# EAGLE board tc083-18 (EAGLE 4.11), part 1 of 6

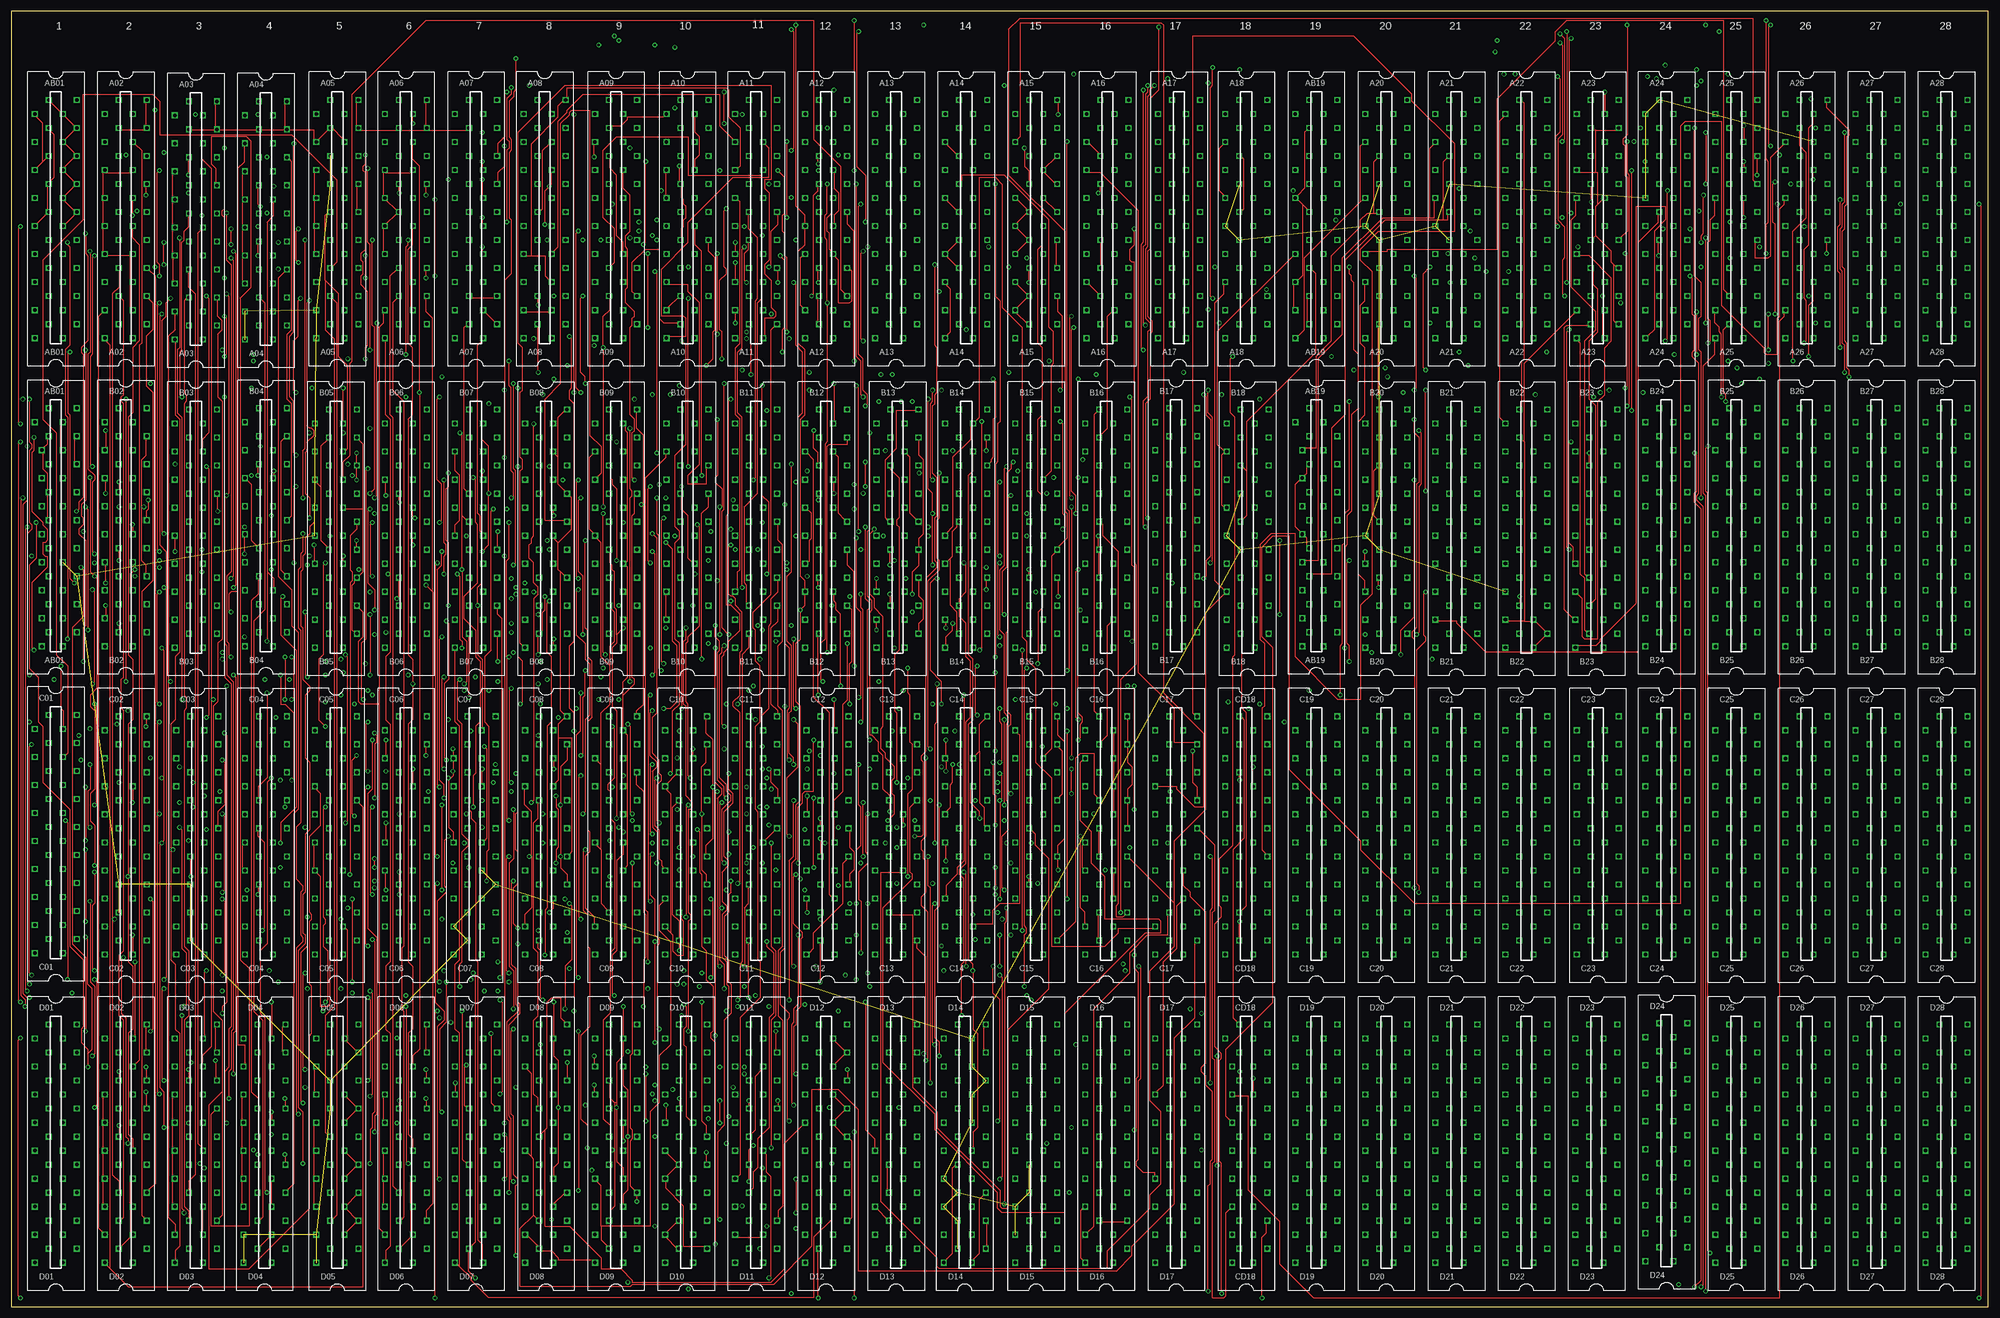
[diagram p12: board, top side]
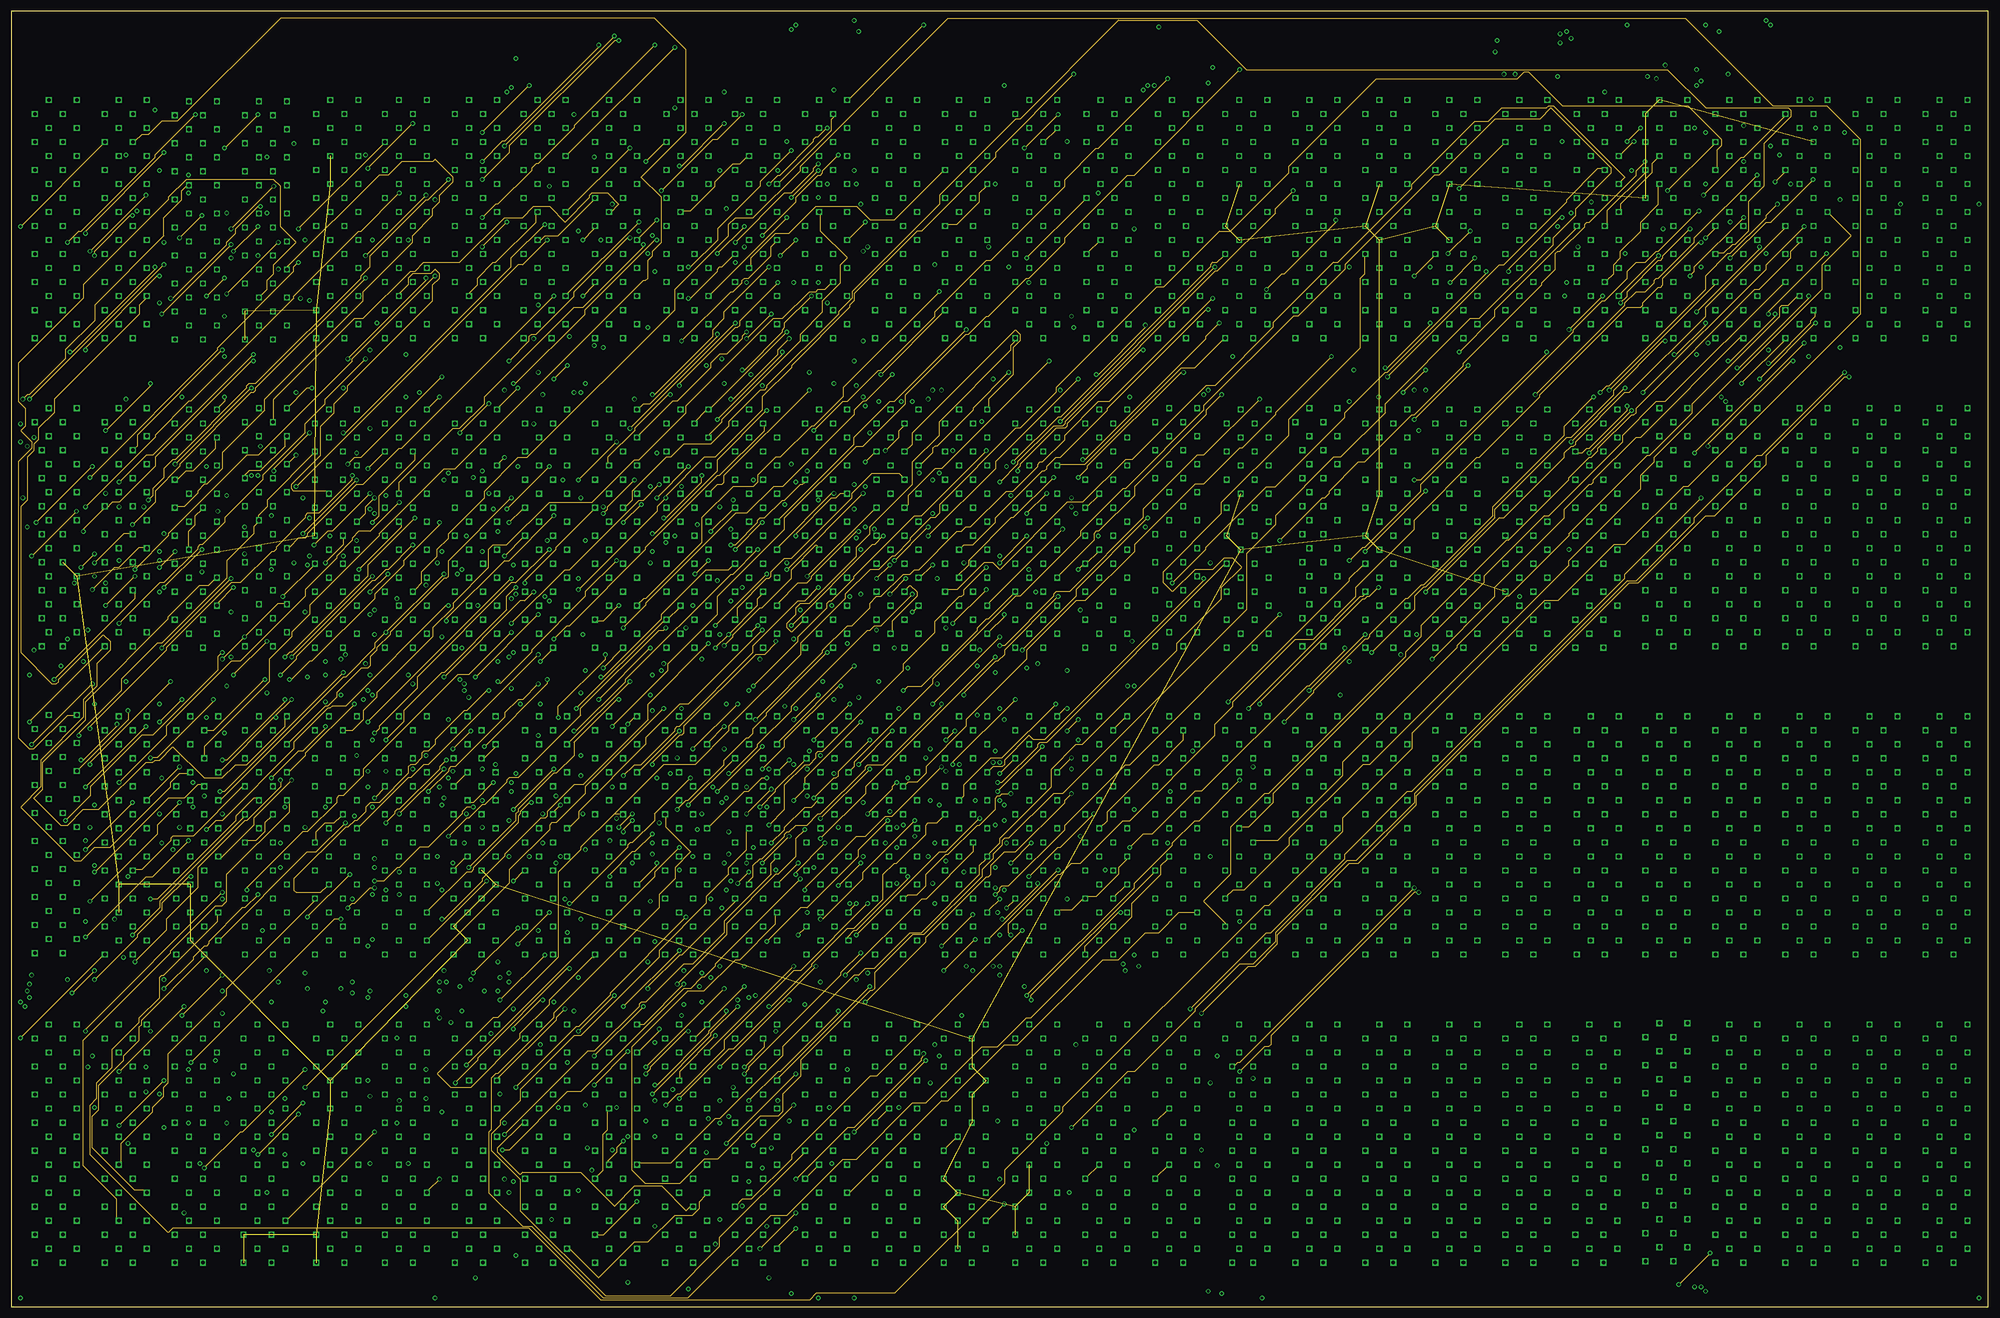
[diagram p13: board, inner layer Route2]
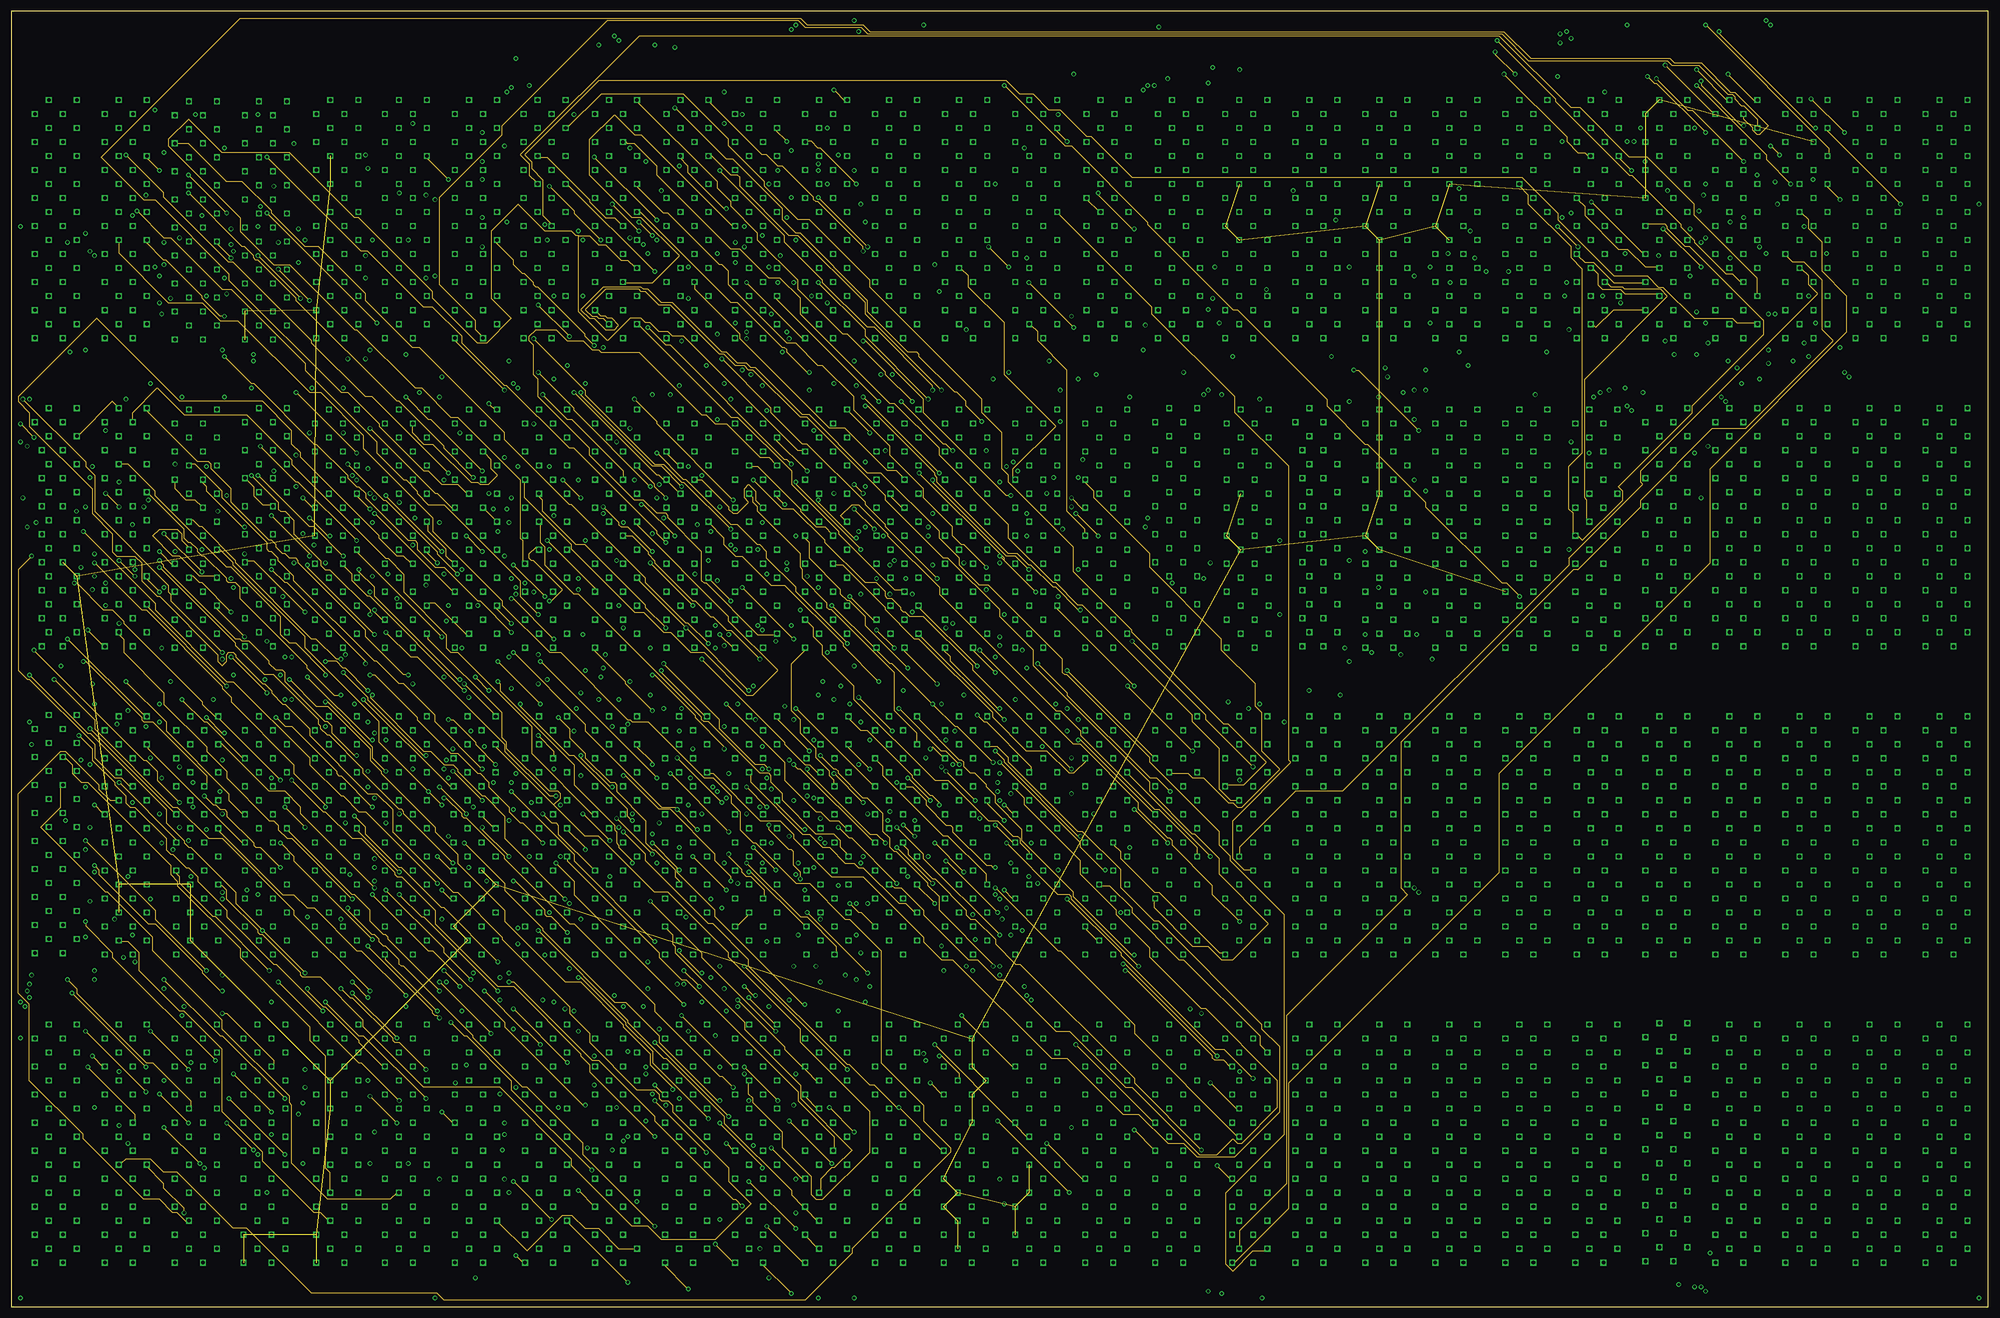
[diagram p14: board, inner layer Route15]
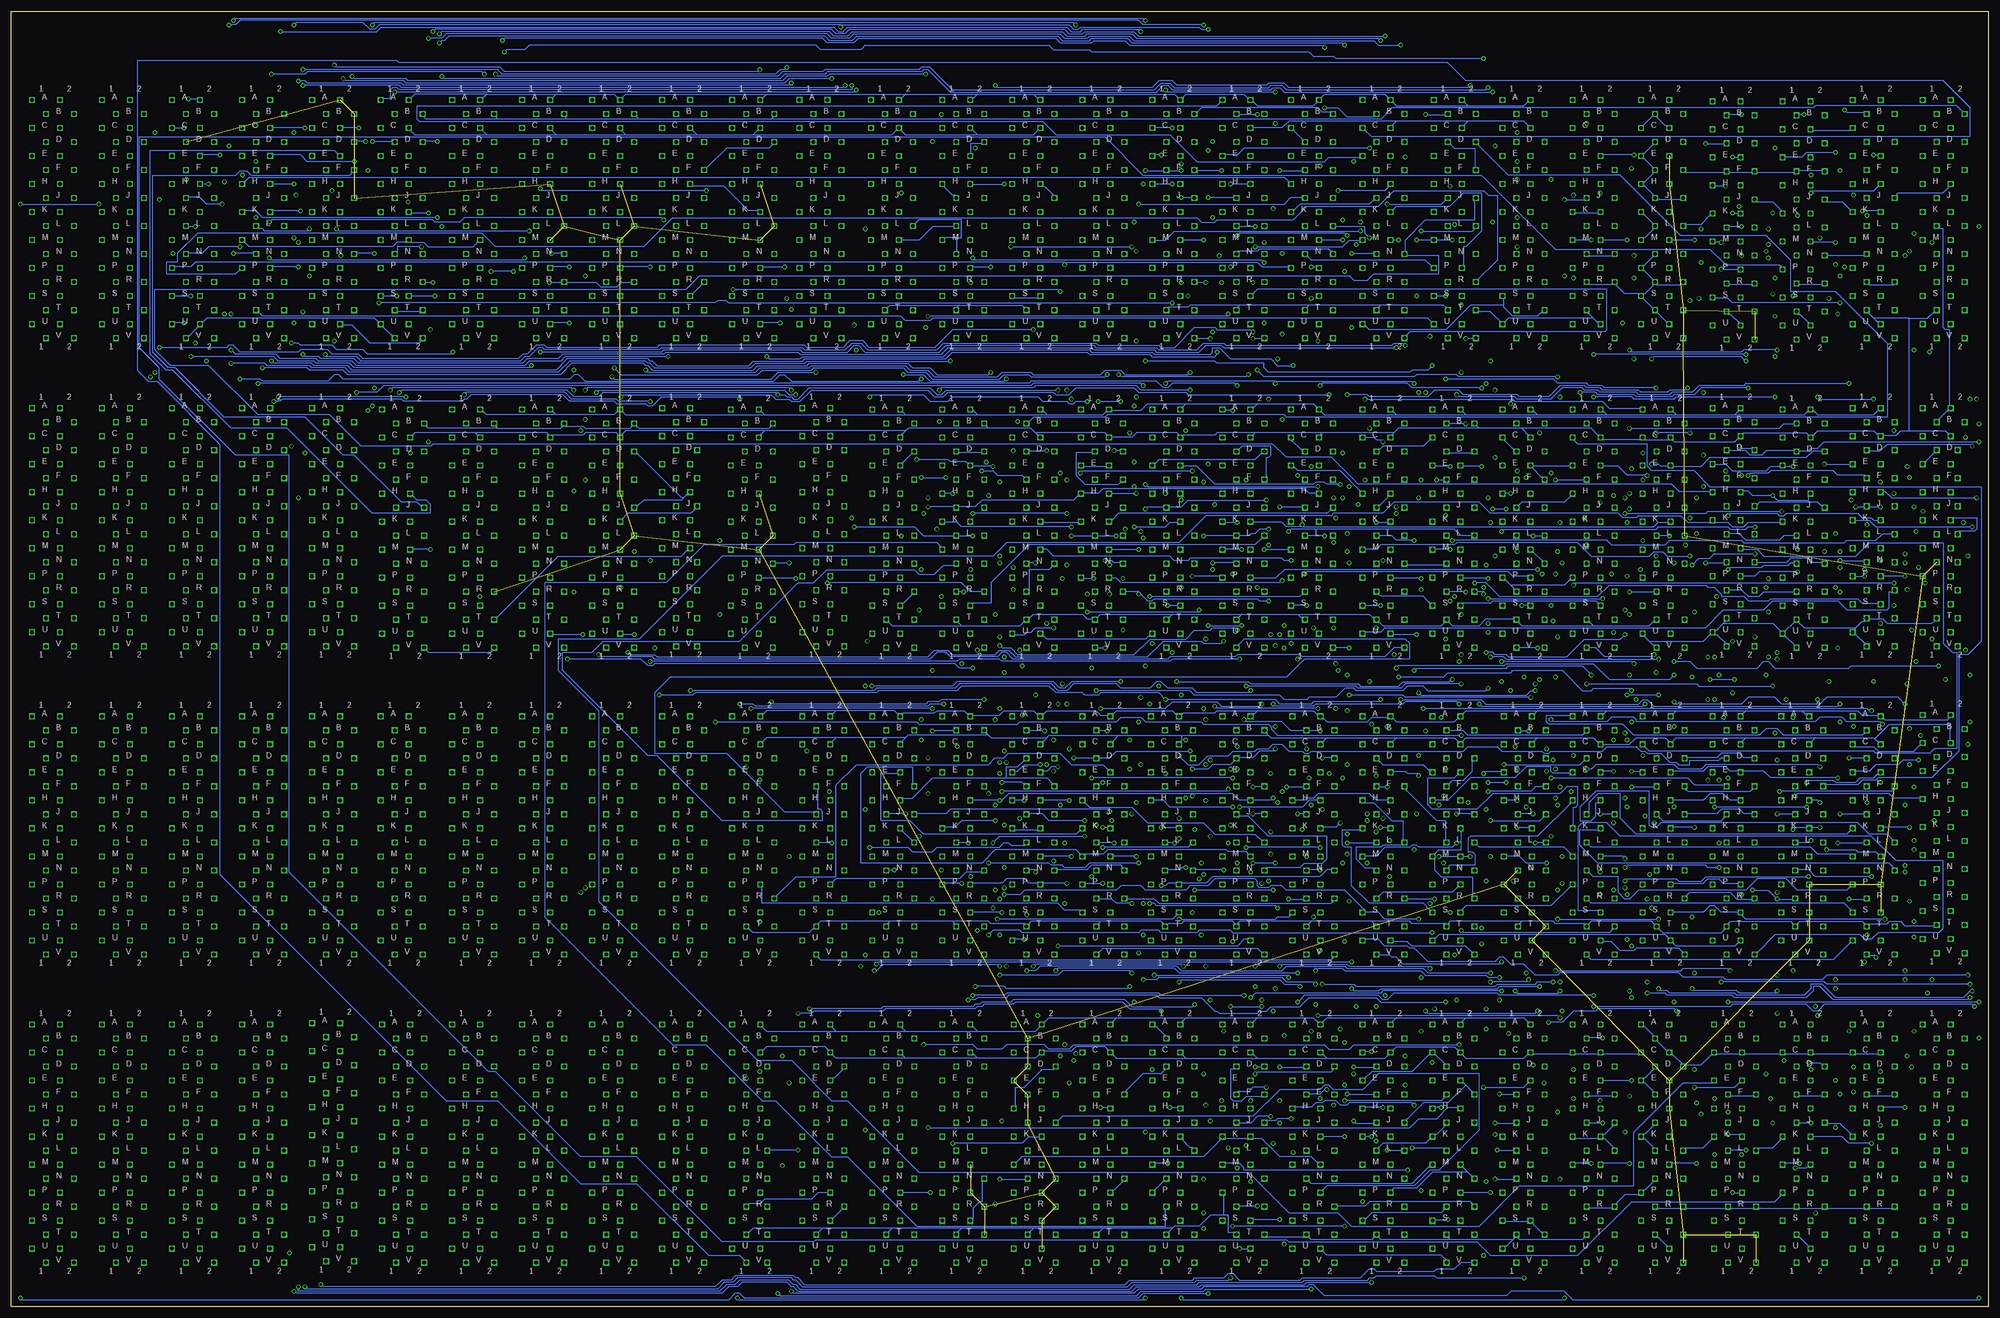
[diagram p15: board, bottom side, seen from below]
Size 448.29 x 293.68 mm. Coordinates in mm from the lower left corner, seen from the top.
Outline: 0,0 448.29,0 448.29,293.68 0,293.68 0,0
Copper layers (1*16): Top 0.035mm / dielectric 1.5mm / Bottom 0.035mm
Design rules "10mils": minimum track width 10mil, minimum drill 24mil, track to track 10mil, track to pad 10mil, pad to pad 10mil, via to via 10mil, smd to smd 10mil, copper to edge 40mil, drill to drill 10mil, minimum pad ring 10mil, minimum via ring 8mil, stop-mask expansion 0mil, vias tented up to drill 0mil, thermal gap 10mil

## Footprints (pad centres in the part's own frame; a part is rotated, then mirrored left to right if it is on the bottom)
H807 = drill 0.813 square: A1 4.763,28.575; A2 -1.587,28.575; B1 1.587,25.4; B2 -4.763,25.4; C1 4.763,22.225; C2 -1.587,22.225; D1 1.587,19.05; D2 -4.763,19.05; E1 4.763,15.875; E2 -1.587,15.875; F1 1.587,12.7; F2 -4.763,12.7; H1 4.763,9.525; H2 -1.587,9.525; J1 1.587,6.35; J2 -4.763,6.35; K1 4.763,3.175; K2 -1.587,3.175; L1 1.587,0; L2 -4.763,0; M1 4.763,-3.175; M2 -1.587,-3.175; N1 1.587,-6.35; N2 -4.763,-6.35; P1 4.763,-9.525; P2 -1.587,-9.525; R1 1.587,-12.7; R2 -4.763,-12.7; S1 4.763,-15.875; S2 -1.587,-15.875; T1 1.587,-19.05; T2 -4.763,-19.05; U1 4.763,-22.225; U2 -1.587,-22.225; V1 1.587,-25.4; V2 -4.763,-25.4
H807-2 = drill 0.813 square: AA1 4.763,60.325; AA2 -1.587,60.325; AB1 1.587,57.15; AB2 -4.763,57.15; AC1 4.763,53.975; AC2 -1.587,53.975; AD1 1.587,50.8; AD2 -4.763,50.8; AE1 4.763,47.625; AE2 -1.587,47.625; AF1 1.587,44.45; AF2 -4.763,44.45; AH1 4.763,41.275; AH2 -1.587,41.275; AJ1 1.587,38.1; AJ2 -4.763,38.1; AK1 4.763,34.925; AK2 -1.587,34.925; AL1 1.587,31.75; AL2 -4.763,31.75; AM1 4.763,28.575; AM2 -1.587,28.575; AN1 1.587,25.4; AN2 -4.763,25.4; AP1 4.763,22.225; AP2 -1.587,22.225; AR1 1.587,19.05; AR2 -4.763,19.05; AS1 4.763,15.875; AS2 -1.587,15.875; AT1 1.587,12.7; AT2 -4.763,12.7; AU1 4.763,9.525; AU2 -1.587,9.525; AV1 1.587,6.35; AV2 -4.763,6.35; BA1 4.763,-9.525; BA2 -1.587,-9.525; BB1 1.587,-12.7; BB2 -4.763,-12.7; BC1 4.763,-15.875; BC2 -1.587,-15.875; BD1 1.587,-19.05; BD2 -3.175,-19.05; BE1 4.763,-22.225; BE2 -1.587,-22.225; BF1 1.587,-25.4; BF2 -3.175,-25.4; BH1 4.763,-28.575; BH2 -1.587,-28.575; BJ1 1.587,-31.75; BJ2 -3.175,-31.75; BK1 4.763,-34.925; BK2 -1.587,-34.925; BL1 1.587,-38.1; BL2 -3.175,-38.1; BM1 4.763,-41.275; BM2 -1.587,-41.275; BN1 1.587,-44.45; BN2 -3.175,-44.45; BP1 4.763,-47.625; BP2 -1.587,-47.625; BR1 1.587,-50.8; BR2 -3.175,-50.8; BS1 4.763,-53.975; BS2 -1.587,-53.975; BT1 1.587,-57.15; BT2 -3.175,-57.15; BU1 4.763,-60.325; BU2 -1.587,-60.325; BV1 1.587,-63.5; BV2 -3.175,-63.5

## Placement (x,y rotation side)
A02  M903  [H807]  26.03,244.94 0 top
A03  M903  [H807]  41.91,244.63 0 top
A04  M903  [H807]  57.78,244.63 0 top
A05  M903  [H807]  73.97,244.94 0 top
A06  M903  [H807]  89.53,244.94 0 top
A07  A07  [H807]  105.41,244.94 0 top
A08  M206X  [H807]  120.96,244.94 0 top
A09  [H807]  137.16,244.94 0 top
A10  [H807]  153.35,244.94 0 top
A11  A11  [H807]  168.91,244.94 0 top
A12  A12  [H807]  184.78,244.94 0 top
A13  H807  [H807]  200.66,244.94 0 top
A14  [H807]  216.53,244.94 0 top
A15  [H807]  232.41,244.94 0 top
A16  [H807]  248.6,244.94 0 top
A17  H807  [H807]  264.79,244.94 0 top
A18  [H807]  280.03,244.94 0 top
A20  [H807]  311.78,244.94 0 top
A21  [H807]  327.65,244.94 0 top
A22  [H807]  343.53,244.94 0 top
A23  [H807]  359.72,244.94 0 top
A24  W023  [H807]  375.28,244.94 0 top
A25  M916  [H807]  391.15,244.94 0 top
A26  M916  [H807]  407.03,244.94 0 top
A27  H807  [H807]  422.9,244.94 0 top
A28  H807  [H807]  438.78,244.94 0 top
AB01  [H807-2]  10.16,213.19 0 top
AB19  [H807-2]  295.9,213.19 0 top
B02  [H807]  26.03,175.09 0 top
B03  [H807]  41.91,174.78 0 top
B04  [H807]  57.78,175.09 0 top
B05  [H807]  73.66,174.78 0 top
B06  B06  [H807]  89.53,174.78 0 top
B07  B07  [H807]  105.41,174.78 0 top
B08  B08  [H807]  121.28,174.78 0 top
B09  M206X  [H807]  137.16,174.78 0 top
B10  B10  [H807]  153.35,174.78 0 top
B11  [H807]  168.91,174.78 0 top
B12  [H807]  184.78,174.78 0 top
B13  M206X  [H807]  200.97,174.78 0 top
B14  M206X  [H807]  216.53,174.78 0 top
B15  [H807]  232.41,174.78 0 top
B16  [H807]  248.28,174.78 0 top
B17  H807  [H807]  264.15,175.09 0 top
B18  [H807]  280.35,174.78 0 top
B20  [H807]  311.78,174.78 0 top
B21  [H807]  327.65,174.78 0 top
B22  [H807]  343.53,174.78 0 top
B23  [H807]  359.4,174.78 0 top
B24  H807  [H807]  375.28,175.09 0 top
B25  H807  [H807]  391.15,175.09 0 top
B26  H807  [H807]  407.03,175.09 0 top
B27  H807  [H807]  422.9,175.09 0 top
B28  H807  [H807]  438.78,175.09 0 top
C01  C01  [H807]  10.16,105.56 0 top
C02  [H807]  26.03,105.25 0 top
C03  [H807]  42.22,105.25 0 top
C04  C04  [H807]  57.78,105.25 0 top
C05  C05  [H807]  73.66,105.25 0 top
C06  C06  [H807]  89.53,105.25 0 top
C07  B07  [H807]  105.09,105.25 0 top
C08  C08  [H807]  121.28,105.25 0 top
C09  M206X  [H807]  137.16,105.25 0 top
C10  [H807]  153.03,105.25 0 top
C11  [H807]  168.91,105.25 0 top
C12  [H807]  185.1,105.25 0 top
C13  [H807]  200.66,105.25 0 top
C14  M206X  [H807]  216.53,105.25 0 top
C15  [H807]  232.41,105.25 0 top
C16  C16  [H807]  248.28,105.25 0 top
C17  C17  [H807]  264.15,105.25 0 top
C19  H807  [H807]  295.9,105.25 0 top
C20  H807  [H807]  311.78,105.25 0 top
C21  H807  [H807]  327.65,105.25 0 top
C22  H807  [H807]  343.53,105.25 0 top
C23  H807  [H807]  359.72,105.25 0 top
C24  H807  [H807]  375.28,105.25 0 top
C25  H807  [H807]  391.15,105.25 0 top
C26  H807  [H807]  407.03,105.25 0 top
C27  H807  [H807]  422.9,105.25 0 top
C28  H807  [H807]  438.78,105.25 0 top
CD18  [H807-2]  280.03,73.5 0 top
D01  H807  [H807]  10.16,35.39 0 top
D02  M903  [H807]  26.03,35.39 0 top
D03  M903  [H807]  41.91,35.39 0 top
D04  M903  [H807]  57.46,35.39 0 top
D05  M903  [H807]  73.97,35.39 0 top
D06  M903  [H807]  89.53,35.39 0 top
D07  D07  [H807]  105.41,35.39 0 top
D08  [H807]  121.28,35.39 0 top
D09  [H807]  137.16,35.39 0 top
D10  [H807]  153.03,35.39 0 top
D11  M206X  [H807]  168.91,35.39 0 top
D12  D12  [H807]  184.78,35.39 0 top
D13  D13  [H807]  200.66,35.39 0 top
D14  [H807]  216.21,35.39 0 top
D15  [H807]  232.41,35.39 0 top
D16  [H807]  248.28,35.39 0 top
D17  D17  [H807]  264.15,35.39 0 top
D19  H807  [H807]  295.9,35.39 0 top
D20  H807  [H807]  311.78,35.39 0 top
D21  H807  [H807]  327.65,35.39 0 top
D22  H807  [H807]  343.53,35.39 0 top
D23  H807  [H807]  359.4,35.39 0 top
D24  H807  [H807]  375.28,35.71 0 top
D25  H807  [H807]  391.15,35.39 0 top
D26  H807  [H807]  407.03,35.39 0 top
D27  H807  [H807]  422.9,35.39 0 top
D28  H807  [H807]  438.78,35.39 0 top

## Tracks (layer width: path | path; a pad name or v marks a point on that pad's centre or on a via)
00\  (via drill 0.61)
  Top 0.254: v106.8,266.15 106.8,264.63 A07.D1 | v342.01,161 342.01,159.47 B22.S2
  Route2 0.254: v106.8,266.15 v117.47,276.82
  Route15 0.254: v225.17,276.82 238.88,263.11 240.41,263.11 257.68,245.83 257.68,245.33 276.98,226.02 278,226.02 298.32,205.7 298.32,204.18 306.95,195.54 307.46,195.54 320.67,182.33 320.67,181.32 337.94,164.05 338.96,164.05 v342.01,161
  Bottom 0.254: v117.47,276.82 117.98,276.31 158.62,276.31 159.63,277.33 163.19,277.33 163.7,276.82 184.02,276.82 185.03,277.84 188.08,277.84 189.61,276.31 224.66,276.31 v225.17,276.82
0_TO_AC\  (via drill 0.61)
  Top 0.254: v81.4,180.81 80.89,180.3 80.89,164.05 82.42,162.52 v82.42,157.95
  Route15 0.254: v81.4,180.81 78.35,183.86 B05.H1 | v82.42,157.95 82.42,157.44 84.45,155.41 B06.T2
0_TO_DTB  (via drill 0.61)
  Top 0.254: v162.68,102.58 v162.68,107.66 | v149.47,120.87 149.98,121.37 149.98,135.09 151.51,136.61 151.51,150.33 150.49,151.35 150.49,173.19 151.51,174.21 151.51,175.73 150.49,176.75 150.49,193 153.03,195.54 153.03,217.89 v152.01,218.91
  Route2 0.254: v152.01,218.91 163.19,230.09 163.7,230.09 165.73,232.12 165.73,232.63 166.24,233.13 167.25,233.13 172.33,238.21 172.33,240.25 173.35,241.26 A11.M1
  Route15 0.254: v162.68,102.58 162.68,102.07 165.73,99.02 165.73,98.51 166.75,97.5 167.76,97.5 170.81,94.45 170.81,92.93 C11.R1 | v162.68,107.66 v149.47,120.87
0_TO_DTB\  (via drill 0.61)
  Top 0.254: 143.38,181.83 143.38,136.61 141.85,135.09 141.85,134.07 C09.A1 | 143.38,181.83 143.38,197.57 141.85,199.1 141.85,203.16 B09.A1 | v140.84,111.72 140.33,112.23 140.33,131.53 v139.82,132.04 | 143.38,181.83 v142.87,181.83 | v160.14,220.43 v160.14,238.72
  Route2 0.254: v140.84,111.72 v137.79,108.67 | v139.82,132.04 141.35,133.57 C09.A1 | v142.87,181.83 v138.81,177.76 | v160.14,238.72 v166.24,244.82 | v160.14,220.43 160.14,219.93 144.9,204.69 143.38,204.69 142.36,203.67 B09.A1
  Route15 0.254: v150.49,174.71 143.38,181.83 v142.87,181.83
  Bottom 0.254: v137.79,108.67 135.76,108.67 C09.K2 | v138.81,177.76 135.76,177.76 B09.K2 | v150.49,174.71 154.55,174.71 B10.L1 | v166.24,244.82 170.3,244.82 A11.L1
0_TO_EF
  Route2 0.254: A10.K2 152.01,248.37 154.05,248.37 159.63,253.96 159.63,254.98 163.7,259.04 165.22,259.04 166.75,260.57 A11.E2
0_TO_EF\
  Top 0.254: 117.98,238.21 121.03,238.21 121.03,233.64 122.04,232.63 A08.R1 | 117.98,238.21 116.45,238.21 A08.N2 | 117.98,238.21 117.98,263.61 124.07,269.71 124.07,272.25 125.09,273.27 A08.A1 126.11,273.77 126.11,276.31 162.17,276.31 162.68,275.81 162.68,269.71 165.22,267.17 165.22,258.53 164.71,258.03 A11.F2
0_TO_LPB\
  Top 0.254: 121.03,40.09 121.53,40.6 121.53,69.05 122.55,70.07 124.58,70.07 124.58,65.49 125.6,64.48 D08.A1 | 121.03,40.09 120.01,39.08 D08.K2 | 121.03,40.09 121.03,18.25 126.61,18.25 133.73,11.14 133.73,8.6 138.3,8.6 140.84,6.06 140.84,5.55 172.33,5.55 175.38,8.6 175.38,37.05 179.45,41.11 D12.J2
0_TO_STA
  Bottom 0.254: A10.N2 148.97,239.23 149.47,239.74 165.22,239.74 165.73,239.23 170.3,239.23 A11.N1
0_TO_STA\  (via drill 0.61)
  Top 0.254: 102.23,179.29 103.25,178.27 B07.K2 | 102.23,179.29 102.23,197.57 v101.72,198.08 | v102.74,141.19 103.25,141.69 103.25,150.84 102.23,151.85 v102.23,167.09 102.23,179.29 | v173.86,232.12 173.86,235.17 A11.P1
  Route2 0.254: v101.72,198.08 v108.33,204.69 | v173.86,232.12 165.22,223.48 165.22,222.47 164.71,221.96 164.21,221.96 151.51,209.26 v151.51,208.75 | v114.93,208.24 110.36,203.67 B07.A1
  Route15 0.254: v108.33,204.69 109.85,203.16 B07.A1 | v102.74,141.19 109.85,134.07 C07.A1
  Bottom 0.254: v102.23,167.09 159.63,167.09 161.67,165.06 166.75,165.06 B11.P2 | v151.51,208.75 151,209.26 131.69,209.26 130.68,208.24 v114.93,208.24
0_TO_STATE\
  Route15 0.254: CD18.AV2 274.95,80.23 273.93,80.23 260.22,93.94 259.2,93.94 251.58,101.56 251.58,103.09 250.06,104.61 C16.L1
0_TO_W\  (via drill 0.61)
  Top 0.254: v271.9,50.76 271.9,89.88 272.41,90.39 272.41,101.56 v271.9,102.07
  Route15 0.254: v271.9,50.76 278,44.67 CD18.BH2 | v271.9,102.07 253.11,120.87 C16.E1
01\  (via drill 0.61)
  Top 0.254: v350.64,244.82 350.64,245.33 350.13,245.83 350.13,265.14 351.15,266.15 351.15,278.35 v350.64,278.85 | v112.39,275.3 111.88,274.79 111.88,265.14 110.36,263.61 110.36,261.07 A07.E1
  Route15 0.254: v350.64,244.82 v355.21,240.25
  Bottom 0.254: v355.21,240.25 360.8,240.25 360.8,239.23 A23.N1 | v350.64,278.85 350.13,278.35 273.93,278.35 272.92,279.36 263.77,279.36 263.27,279.87 241.93,279.87 241.42,280.38 240.41,280.38 235.33,275.3 188.59,275.3 187.07,276.82 186.05,276.82 185.03,275.81 162.68,275.81 162.17,276.31 160.65,276.31 159.63,275.3 v112.39,275.3
1_TO_DF  (via drill 0.61)
  Top 0.254: C12.L1 186.56,105.63 186.56,111.21 C12.J1 186.56,112.23 186.56,114.77 188.59,116.8 188.59,136.61 189.61,137.63 v189.61,150.33 | v145.92,234.66 146.43,234.15 v146.43,193.51 | v177.92,52.79 177.41,53.3 177.41,63.46 177.92,63.97 177.92,67.02 178.94,68.03 178.94,83.27 179.45,83.78 179.45,84.8 177.41,86.83 177.41,97.5 v177.92,98.01
  Route2 0.254: v177.92,52.79 v162.17,37.05 | v177.92,98.01 177.92,98.51 v184.53,105.12
  Route15 0.254: v145.92,234.66 126.11,254.47 A08.H1 | v146.43,193.51 152.52,187.41 153.03,187.41 163.19,177.25 164.71,177.25 169.29,172.68 169.79,172.68 171.32,171.16 171.32,169.63 177.92,163.03 177.92,162.01 v189.61,150.33 | v162.17,37.05 163.7,35.52 D11.L2
  Bottom 0.254: v184.53,105.12 186.05,105.12 C12.L1
1_TO_DTF  (via drill 0.61)
  Top 0.254: v160.65,19.77 160.14,20.28 160.14,39.59 161.67,41.11 161.67,64.99 163.19,66.51 163.19,73.11 162.68,73.62 162.68,78.7 161.67,79.72 161.67,88.35 162.68,89.37 162.68,93.43 163.19,93.94 v163.19,96.48 | v183,163.03 183,165.06 B12.P2
  Route2 0.254: v138.81,120.36 141.35,122.9 142.87,122.9 150.49,130.52 150.49,131.03 151,131.53 151.51,131.53 168.27,148.3 168.27,149.82 178.43,159.98 179.95,159.98 v183,163.03
  Route15 0.254: v163.19,96.48 163.19,97.5 159.63,101.05 159.63,102.58 149.47,112.74 146.93,112.74 139.31,120.36 v138.81,120.36
  Bottom 0.254: v160.65,19.77 166.75,19.77 D11.S2
02\  (via drill 0.61)
  Top 0.254: v106.8,255.49 106.8,251.93 A07.J1 | v351.15,288.51 352.17,287.49 352.17,264.63 v351.66,264.12
  Route2 0.254: v106.8,255.49 112.9,261.58 112.9,263.11 136.77,286.98 v137.79,286.98
  Bottom 0.254: v137.79,286.98 138.3,287.49 193.16,287.49 194.18,288.51 204.34,288.51 204.85,288 208.91,288 209.93,289.01 257.68,289.01 258.69,288 261.74,288 262.76,289.01 350.64,289.01 v351.15,288.51 | v351.66,264.12 354.71,264.12 A23.D2
03\  (via drill 0.61)
  Top 0.254: v106.8,240.25 106.8,239.23 A07.N1 | v112.39,245.83 112.39,262.09 112.9,262.6 112.9,264.12 112.39,264.63 112.39,273.77 113.41,274.79 v113.41,276.31
  Route2 0.254: v112.39,245.83 v106.8,240.25
  Route15 0.254: v338.45,279.36 352.67,265.14 352.67,264.12 355.21,261.58 356.74,261.58 357.75,260.57 A23.E2
  Bottom 0.254: v113.41,276.31 113.91,275.81 159.13,275.81 160.14,276.82 162.68,276.82 163.19,276.31 184.53,276.31 185.54,277.33 187.57,277.33 189.1,275.81 234.82,275.81 239.9,280.89 241.93,280.89 242.44,280.38 263.77,280.38 264.28,279.87 273.43,279.87 274.44,278.85 337.94,278.85 v338.45,279.36
04\  (via drill 0.61)
  Top 0.254: v353.69,247.87 353.18,248.37 353.18,286.98 v353.69,287.49 | v106.8,259.55 106.8,258.03 A07.F1
  Route2 0.254: v133.22,285.97 133.22,285.46 111.88,264.12 111.37,264.12 v106.8,259.55
  Bottom 0.254: v353.69,247.87 357.75,247.87 A23.K2 | v353.69,287.49 350.64,287.49 349.63,288.51 263.27,288.51 262.25,287.49 258.19,287.49 257.17,288.51 210.43,288.51 209.42,287.49 204.34,287.49 203.83,288 194.69,288 193.67,286.98 139.31,286.98 138.3,285.97 v133.22,285.97
05\  (via drill 0.61)
  Route2 0.254: v328.29,216.37 336.42,224.5 336.42,226.02 354.71,244.31 A23.L2
  Route15 0.254: v132.2,217.89 130.17,219.93 130.17,220.43 119.5,231.1 118.99,231.1 118.49,231.61 118.49,232.12 116.45,234.15 115.95,234.15 113.91,236.18 113.91,237.2 109.85,241.26 A07.M1
  Bottom 0.254: v132.2,217.89 132.71,218.4 134.74,218.4 135.25,217.89 172.84,217.89 173.35,218.4 177.92,218.4 179.45,216.88 188.08,216.88 188.59,217.39 202.31,217.39 202.81,217.89 236.34,217.89 237.87,216.37 254.63,216.37 256.15,217.89 257.17,217.89 258.69,216.37 268.85,216.37 269.36,216.88 300.35,216.88 300.86,216.37 v328.29,216.37
06\  (via drill 0.61)
  Top 0.254: v352.67,289.01 v352.67,232.12 | v111.88,263.11 111.88,258.53 110.36,257.01 110.36,254.98 A07.H1
  Route2 0.254: v136.77,288 v111.88,263.11
  Bottom 0.254: v352.67,232.12 354.71,232.12 A23.R2 | v352.67,289.01 352.17,289.52 262.25,289.52 261.23,288.51 259.2,288.51 258.19,289.52 209.42,289.52 208.4,288.51 205.35,288.51 204.85,289.01 193.67,289.01 192.65,288 v136.77,288
07\  (via drill 0.61)
  Top 0.254: v352.17,229.07 351.66,229.58 351.66,237.2 352.17,237.71 352.17,244.82 350.64,246.34 350.64,264.63 351.66,265.65 351.66,285.97 v351.15,286.47 | v106.8,246.85 106.8,245.33 A07.L1
  Route2 0.254: v145.92,285.97 127.63,267.68 127.63,267.17 119.5,259.04 118.99,259.04 117.98,258.03 117.98,257.52 110.36,249.9 109.85,249.9 v106.8,246.85
  Bottom 0.254: v352.17,229.07 357.75,229.07 A23.S2 | v351.15,286.47 350.64,286.98 350.13,286.98 349.12,288 263.77,288 262.76,286.98 257.68,286.98 256.66,288 210.94,288 209.93,286.98 203.83,286.98 203.32,287.49 195.19,287.49 194.18,286.47 146.43,286.47 v145.92,285.97
76
  Bottom 0.254: C04.V2 52.45,80.23 48.38,84.29 29.08,84.29 28.06,83.27 26.54,83.27 25.01,84.8 11.3,84.8 10.28,85.81 10.28,101.05 20.95,101.05 26.54,106.64 83.43,106.64 86.48,109.69 92.07,109.69 93.09,108.67 93.09,89.88 88.51,89.88 C06.S2
76+77  (via drill 0.61)
  Route2 0.254: v82.42,94.96 81.4,94.96 77.85,91.4 77.34,91.4 v76.32,90.39
  Route15 0.254: v82.42,94.96 65.65,111.72 65.65,113.25 62.1,116.8 58.54,116.8 47.37,127.98 C03.C1 | v76.32,90.39 76.32,89.88 81.91,84.29 82.42,84.29 83.43,83.27 83.43,82.77 84.45,81.75 84.96,81.75 88.01,78.7 88.01,77.69 88.51,77.18 89.02,77.18 104.77,61.43 104.77,60.92 115.95,49.75 116.96,49.75 129.66,37.05 129.66,34.51 v145.92,18.25 | v171.32,18.25 179.45,10.12 D12.V2
  Bottom 0.254: v145.92,18.25 v171.32,18.25
76\  (via drill 0.61)
  Route15 0.254: v119.5,85.31 139.82,64.99 139.82,64.48 147.95,56.35 148.46,56.35 161.67,43.14 161.67,41.62 176.91,26.38 176.91,25.36 179.45,22.82 D12.R2 179.95,22.31 183,19.27 D12.S2
  Bottom 0.254: v119.5,85.31 118.99,84.8 85.97,84.8 84.96,85.81 C06.T2
77
  Bottom 0.254: C05.V2 69.21,80.23 70.23,81.24 79.88,81.24 80.39,80.73 83.43,80.73 85.47,82.77 87.5,82.77 C06.U2
77\  (via drill 0.61)
  Top 0.254: v96.64,67.02 96.13,66.51 v96.13,1.99 | v183,1.99 183,12.66 D12.U2
  Route15 0.254: v96.64,67.02 84.96,78.7 84.96,79.21 C06.V2 | D12.T2 179.95,16.22 183,13.17 D12.U2
  Bottom 0.254: v96.13,1.99 96.64,1.49 182.49,1.49 v183,1.99
+3V@A09U1
  Top 0.254: A08.K2 120.01,248.37 120.52,248.88 120.52,262.09 122.04,263.61 A08.D1 | A07.S2 104.26,228.56 109.85,228.56 A07.S1
  Route2 0.254: B13.U2 199.77,152.87 199.77,155.41 205.35,161 205.35,162.01 203.83,163.54 202.81,162.52 B13.R1 | A08.K2 118.99,247.87 118.99,245.83 109.85,236.69 109.34,236.69 105.79,233.13 105.79,231.61 103.75,229.58 A07.S2
  Route15 0.254: B13.R1 202.31,162.52 200.27,162.52 187.57,175.22 187.57,175.73 176.91,186.4 176.91,189.45 164.71,201.64 163.19,201.64 142.36,222.47 A09.U1
  Bottom 0.254: A08.F2 116.45,258.03 116.45,262.6 121.03,262.6 122.04,263.61 A08.D1 | 109.85,227.04 109.85,228.56 A07.S1 | 109.85,227.04 109.85,226.53 107.82,224.5 102.23,224.5 101.21,225.51 A07.T2 | 109.85,227.04 117.47,227.04 123.06,221.45 140.33,221.45 141.35,222.47 A09.U1
+3V@B12U1
  Top 0.254: 212.97,169.63 213.48,170.14 213.48,175.73 214.5,176.75 214.5,177.76 B14.K2 | 212.97,169.63 211.96,168.62 B14.N2 | 212.97,169.63 212.97,158.97 214.5,157.44 214.5,152.87 B14.U2 | B13.K1 205.35,178.27 203.83,179.79 203.83,192.49 202.81,193.51 B13.D1
  Route2 0.254: B14.A1 221.61,203.67 221.61,205.7 227.2,211.29 227.2,217.39 228.72,218.91 228.72,220.43 227.71,221.45 204.34,198.08 204.34,195.54 202.81,194.02 B13.D1
  Bottom 0.254: B12.U1 190.11,152.36 191.13,151.35 213.48,151.35 214.5,152.36 B14.U2 | B14.R1 217.55,162.52 217.55,167.09 212.97,167.09 211.96,168.11 B14.N2 | B13.K1 206.37,177.76 214.5,177.76 B14.K2 | B13.F2 196.72,186.91 197.23,186.4 204.85,186.4 206.88,188.43 206.88,193.51 202.81,193.51 B13.D1
+3V@C08U1
  Top 0.254: C05.L2 68.7,104.61 68.7,99.53 C05.N2 69.21,98.51 70.23,97.5 70.23,68.03 71.75,68.03 72.26,68.54 72.26,82.77 C05.U2 | C04.N2 52.45,99.53 52.45,104.61 C04.L2
  Route2 0.254: C04.L2 53.46,105.63 55.49,105.63 57.53,107.66 57.53,109.69 59.05,111.21 C04.J1 | C05.L2 69.21,105.63 69.21,107.66 71.24,109.69 73.27,109.69 74.8,111.21 C05.J1
  Route15 0.254: C02.C1 31.11,126.96 31.11,126.45 52.45,105.12 C04.L2
  Bottom 0.254: C04.U2 56.51,82.77 57.53,81.75 70.73,81.75 71.75,82.77 C05.U2 72.26,83.27 73.27,84.29 124.58,84.29 125.6,83.27 C08.U1 | C01.C1 15.36,127.47 16.89,125.95 25.01,125.95 26.03,126.96 30.6,126.96 C02.C1 | C04.J1 59.56,111.21 60.57,110.2 73.78,110.2 74.8,111.21 C05.J1
+3V@C15U1
  Top 0.254: 219.58,125.95 219.58,132.04 221.1,133.57 C14.A1 | 219.58,125.95 218.56,124.93 C14.D1 | 219.58,125.95 219.58,114.26 220.59,113.25 220.59,109.18 221.1,108.67 C14.K1 | C15.U1 237.36,83.27 241.42,87.34 241.42,124.42 242.44,125.44 245.49,125.44 245.49,116.29 246.5,115.28 C16.H2
  Bottom 0.254: C14.K2 215.51,108.17 221.1,108.17 C14.K1 | 222.63,119.85 213.48,119.85 211.96,118.33 C14.F2 | 222.63,119.85 222.63,122.39 220.09,122.39 218.56,123.91 C14.D1 | 222.63,119.85 239.39,119.85 243.96,115.28 246.5,115.28 C16.H2
+3V@D09U1
  Route15 0.254: D09.U1 141.35,13.17 137.79,13.17 133.22,17.74 130.17,17.74 127.12,20.79 125.09,20.79 116.96,12.66 110.36,19.27 D07.S1
  Bottom 0.254: D07.T2 101.21,16.73 103.75,19.27 D07.S2 104.26,19.27 109.85,19.27 D07.S1
+3V@D10U1
  Top 0.254: D10.U1 157.6,13.68 152.52,13.68 152.52,22.82 148.46,26.89 148.46,28.41 D10.N2 148.46,29.43 151,31.97 D10.M2 151,32.47 148.46,35.01 D10.L2 | D11.D1 170.3,53.81 168.78,52.29 168.78,40.09 167.76,39.08 D11.K2
  Bottom 0.254: D11.F2 164.71,47.71 168.27,47.71 169.29,46.7 171.32,46.7 171.83,47.21 171.83,53.81 170.81,53.81 D11.D1 | D14.M1 220.59,32.47 219.07,34 177.92,34 173.86,38.06 D11.K1 173.35,38.06 167.76,38.06 D11.K2 166.75,38.06 164.71,38.06 160.65,34 153.54,34 152.01,32.47 D10.M2
-15V
  Top 0.254: 7.23,259.55 8.25,260.57 AB01.AE2 | 7.23,259.55 5.71,258.03 AB01.AF2 | 7.23,259.55 7.23,268.19 5.71,269.71 AB01.AB2 | B22.B2 338.45,200.62 337.43,201.64 337.43,268.69 338.45,269.71 A22.B2
  Bottom 0.254: B18.B2 275.97,199.61 276.47,199.1 305.94,199.1 306.45,199.61 B20.B2 307.46,199.61 307.97,199.1 318.13,199.1 318.64,199.61 322.7,199.61 B21.B2 323.21,199.61 323.72,199.1 337.94,199.1 | 337.94,199.1 338.45,199.61 B22.B2 | 337.94,199.1 353.69,199.1 354.2,199.61 B23.B2 | 275.97,269.2 275.46,269.71 A18.B2 | 275.97,269.2 305.94,269.2 | 305.94,269.2 306.45,269.71 A20.B2 | 322.19,269.2 322.7,269.71 A21.B2 | 305.94,269.2 322.19,269.2 | 337.94,269.2 338.45,269.71 A22.B2 | 322.19,269.2 337.94,269.2 | 337.94,269.2 354.2,269.2 354.71,269.71 A23.B2 | 275.97,269.2 137.79,269.2 135.25,271.74 39.75,271.74 39.24,272.25 7.23,272.25 5.71,270.73 AB01.AB2
-ADDR_ACC\  (via drill 0.61)
  Top 0.254: v2.15,60.92 1.65,60.41 1.65,2.5 v2.15,1.99 | v271.39,3.52 271.39,27.39 271.9,27.9 271.9,32.98 272.41,33.49 272.41,48.73 270.89,50.25 270.89,52.29 269.87,53.3 269.87,54.32 270.89,55.33 270.89,89.37 267.33,92.93 267.33,93.94 265.81,95.47 265.81,98.51 C17.N1
  Route2 0.254: v2.15,60.92 20.95,79.72 C02.V2
  Bottom 0.254: v2.15,1.99 2.66,1.49 94.1,1.49 96.13,3.52 108.33,3.52 109.34,2.5 150.49,2.5 153.03,5.04 154.05,5.04 154.55,4.53 177.92,4.53 178.43,4.03 192.65,4.03 193.67,3.01 270.89,3.01 v271.39,3.52
-SH_EN  (via drill 0.61)
  Top 0.254: C10.C1 157.6,126.96 157.6,123.41 156.59,122.39 v156.59,111.72 156.59,99.02 157.6,98.01 157.6,95.97 C10.P1 | v166.75,232.12 166.24,232.63 166.24,238.72 167.25,239.74 167.25,241.26 A11.M2 | v161.67,131.53 161.16,132.04 161.16,147.28 161.67,147.79 161.67,148.3 162.68,149.31 162.68,150.84 165.22,153.38 165.22,156.93 163.19,158.97 162.17,158.97 162.17,179.29 162.68,179.79 162.68,205.19 v163.19,205.7
  Route2 0.254: v161.67,131.53 158.11,127.98 C10.C1 | v163.19,205.7 163.7,205.7 173.86,215.86 173.86,216.88 v176.4,219.42
  Route15 0.254: v166.75,232.12 179.45,219.42 A12.V2
  Bottom 0.254: v156.59,111.72 155.06,111.72 C10.J1 | v176.4,219.42 179.45,219.42 A12.V2
-TM_EN
  Bottom 0.254: B15.D2 228.21,193.51 233.8,193.51 B15.D1
-U+M_DY  (via drill 0.61)
  Top 0.254: v180.46,89.37 180.46,91.91 C12.R2 | v224.15,75.15 224.66,74.64 224.66,29.43 v224.15,28.92
  Route15 0.254: v194.18,75.65 v180.46,89.37
  Bottom 0.254: v194.18,75.65 194.69,76.16 209.93,76.16 210.94,75.15 v224.15,75.15 | v224.15,28.92 218.05,28.92 D14.N1
-WRITE_OK  (via drill 0.61)
  Top 0.254: v241.93,128.49 242.44,128.99 242.44,132.04 242.95,132.55 242.95,133.57 241.93,134.58 241.93,157.44 v242.44,157.95 | v193.67,204.18 194.18,204.69 194.18,206.72 193.16,207.73 193.16,214.85 192.15,215.86 192.15,249.39 v192.65,249.9
  Route15 0.254: v241.93,128.49 242.44,128.49 259.2,111.72 C17.J2 | v242.44,157.95 241.93,157.95 236.85,163.03 236.34,163.03 231.26,168.11 230.75,168.11 228.21,170.65 226.18,170.65 209.93,186.91 209.93,187.92 209.42,188.43 209.42,188.94 194.18,204.18 v193.67,204.18
  Bottom 0.254: v192.65,249.9 159.63,249.9 158.11,251.42 155.57,251.42 A10.J1
-XSTA\
  Top 0.254: D13.M2 198.75,31.97 198.75,26.38 D13.P2
  Bottom 0.254: D13.N2 196.21,28.41 198.24,26.38 198.75,26.38 D13.P2
B-BRK  (via drill 0.61)
  Top 0.254: B10.S2 152.01,158.46 152.01,152.87 B10.U2 152.01,152.36 v152.01,135.6 | v176.4,42.13 175.89,42.63 175.89,64.99 176.4,65.49 176.4,66.51 174.37,68.54 174.37,80.23 175.38,81.24 v175.38,136.11 | B10.R2 148.46,161.51 148.46,155.92 B10.T2
  Route2 0.254: v26.54,135.09 26.54,133.06 15.36,121.88 C01.E1 | v128.14,135.6 148.46,155.92 B10.T2 148.97,155.92 151.51,158.46 B10.S2
  Route15 0.254: v176.4,42.13 v186.05,32.47
  Bottom 0.254: v186.05,32.47 189.1,32.47 D12.M1 | v175.38,136.11 174.87,135.6 v152.01,135.6 | v26.54,135.09 27.05,135.09 27.55,135.6 v128.14,135.6
B-BRK\  (via drill 0.61)
  Top 0.254: v21.46,184.37 21.46,187.41 B02.F2 | 29.59,181.32 29.59,169.13 30.6,168.11 30.6,166.08 B02.P1 | 29.59,181.32 29.59,191.99 30.6,193 30.6,197.07 B02.C1 | v33.65,136.61 33.14,137.12 33.14,161.51 v33.65,162.01 | v21.46,158.97 21.46,156.43 B02.T2 | v24.51,169.13 24.51,171.67 B02.M2 | 29.59,181.32 v30.09,181.32
  Route2 0.254: v133.22,137.63 v144.9,149.31 | v28.06,165.57 v21.46,158.97
  Route15 0.254: v24.51,181.32 v21.46,184.37 | v33.65,162.01 30.6,165.06 B02.P1 | v28.06,165.57 v24.51,169.13
  Bottom 0.254: v24.51,181.32 27.05,181.32 B02.J1 28.06,181.32 v30.09,181.32 | v144.9,149.31 147.95,149.31 B10.V2 | v133.22,137.63 114.93,137.63 113.91,136.61 79.37,136.61 78.35,137.63 77.34,137.63 75.81,136.11 34.16,136.11 v33.65,136.61 | v28.06,165.57 30.6,165.57 B02.P1
B-RUN  (via drill 0.61)
  Top 0.254: v11.3,145.25 11.3,135.6 11.81,135.09 11.81,131.53 C01.B1
  Route2 0.254: v133.73,142.71 134.23,142.71 147.44,155.92 147.44,156.93 157.6,167.09 162.68,167.09 163.7,168.11 B11.N2
  Route15 0.254: v71.24,146.27 73.78,146.27 75.31,144.74 75.81,144.74 v80.89,139.66
  Bottom 0.254: v11.3,145.25 31.11,145.25 31.62,144.74 48.38,144.74 49.91,146.27 50.92,146.27 52.45,144.74 66.16,144.74 67.69,146.27 v71.24,146.27 | v80.89,139.66 81.4,140.17 89.53,140.17 90.04,139.66 92.07,139.66 96.64,144.23 107.82,144.23 108.33,143.73 122.55,143.73 123.57,142.71 v133.73,142.71
B-XSTA  (via drill 0.61)
  Top 0.254: v166.24,77.18 166.24,90.39 167.25,91.4 167.25,95.47 C11.P2 | v189.61,53.81 189.61,51.78 D12.E1 | v162.17,248.88 161.67,248.37 161.67,235.67 162.17,235.17 162.17,234.15 160.65,232.63 160.65,221.45 161.16,220.94 v161.16,214.85 | v209.93,165.06 209.42,165.06 208.4,164.05 208.4,144.23 210.94,141.69 v210.94,136.61
  Route2 0.254: v210.94,136.61 210.94,136.11 197.73,122.9 194.18,122.9 193.67,122.39 193.67,121.88 183.51,111.72 183,111.72 180.46,109.18 177.92,109.18 176.4,107.66 175.89,107.66 175.38,107.15 175.38,106.64 170.3,101.56 169.79,101.56 168.27,100.04 168.27,97.5 166.75,95.97 C11.P2
  Route15 0.254: v166.24,77.18 v189.61,53.81 | v162.17,248.88 161.67,248.88 153.54,257.01 153.54,258.53 151.51,260.57 A10.E2 | v161.16,214.85 172.33,203.67 172.33,202.65 179.45,195.54 180.46,195.54 193.67,182.33 193.67,181.83 198.24,177.25 198.24,176.75 v209.93,165.06
BAC_00
  Route15 0.254: B06.B1 91.05,199.61 91.05,198.08 93.59,195.54 95.63,195.54 104.26,186.91 105.79,186.91 106.29,186.4 108.33,186.4 110.36,188.43 108.83,189.95 108.83,191.99 107.31,193.51 B07.D1
  Bottom 0.254: B07.C1 109.85,196.56 107.31,194.02 B07.D1
BAC_00\  (via drill 0.61)
  Top 0.254: v97.15,177.76 97.66,178.27 97.66,186.4 96.64,187.41 96.64,205.7 v97.15,206.21
  Route2 0.254: v57.53,142.2 45.84,130.52 44.32,130.52 C03.B1 | v63.11,142.2 63.62,142.2 67.69,146.27 68.19,146.27 82.42,160.49 82.42,161.51 89.02,168.11 89.02,169.13 97.15,177.25 v97.15,177.76 | v97.15,206.21 94.61,203.67 B06.A1
  Route15 0.254: v149.98,49.24 149.98,49.75 144.9,54.83 144.9,57.37 138.81,63.46 138.81,63.97 129.15,73.62 125.6,73.62 111.88,87.34 111.88,89.88 101.21,100.55 101.21,102.58 96.13,107.66 96.13,108.67 83.94,120.87 83.94,121.37 81.4,123.91 81.4,126.45 71.75,136.11 69.21,136.11 v63.11,142.2
  Bottom 0.254: v63.11,142.2 v57.53,142.2 | v149.98,49.24 150.49,49.24 151.51,48.22 154.05,48.22 D10.F1
BAC_01
  Bottom 0.254: B07.F2 101.21,187.92 103.75,190.46 B07.E2 103.25,190.46 94.61,190.46 B06.E1
BAC_01\  (via drill 0.61)
  Top 0.254: v63.62,137.63 64.13,138.14 64.13,146.77 v63.62,147.28 | v81.91,165.57 81.4,166.08 81.4,177.25 v81.91,177.76 | v81.91,93.43 81.4,93.94 81.4,112.74 v81.91,113.25
  Route2 0.254: v63.62,137.63 59.56,133.57 | 59.56,133.57 47.37,121.37 C03.E1 | v81.91,165.57 v63.62,147.28 | v81.91,177.76 83.43,179.29 83.43,183.86 91.56,191.99 91.56,193.51 B06.D1 | 59.56,133.57 v60.07,133.57
  Route15 0.254: v130.17,45.68 129.66,45.68 111.88,63.46 111.88,64.48 95.63,80.73 94.61,80.73 v81.91,93.43 | v81.91,113.25 74.8,120.36 74.29,120.36 73.78,120.87 73.78,121.37 63.62,131.53 62.1,131.53 v60.07,133.57
  Bottom 0.254: v130.17,45.68 130.68,46.19 144.9,46.19 145.41,45.68 146.93,45.68 147.95,46.7 150.49,46.7 151,46.19 152.52,46.19 153.54,45.17 157.6,45.17 D10.H1
BAC_02
  Route15 0.254: B07.K1 109.85,178.27 107.31,180.81 B07.J1
  Bottom 0.254: B06.H1 94.61,183.86 96.13,182.33 105.79,182.33 106.8,181.32 B07.J1
BAC_02\  (via drill 0.61)
  Top 0.254: v98.17,166.08 98.17,170.14 98.67,170.65 98.67,172.68 98.17,173.19 v98.17,187.41 | v152.52,68.54 153.03,68.03 153.03,63.46 152.52,62.95 152.52,59.4 153.03,58.89 153.03,43.14 154.05,42.13 D10.J1 | v123.57,100.55 123.57,103.59 124.07,104.1 124.07,112.74 123.57,113.25 v123.57,115.79
  Route2 0.254: v98.17,166.08 v84.96,152.87 82.42,150.33 82.42,149.31 75.81,142.71 75.31,142.71 47.37,114.77 C03.H1
  Route15 0.254: v152.52,68.54 127.63,93.43 127.63,96.48 v123.57,100.55 | v123.57,115.79 122.04,115.79 111.88,125.95 111.88,127.47 92.07,147.28 90.55,147.28 v84.96,152.87
  Bottom 0.254: v98.17,187.41 91.56,187.41 B06.F1
BAC_03
  Route15 0.254: B06.K1 94.61,177.76 94.61,175.73 98.67,171.67 98.67,170.14 100.2,168.62 B07.N2
  Bottom 0.254: B07.M2 103.25,171.16 100.71,168.62 B07.N2
BAC_03\  (via drill 0.61)
  Top 0.254: v47.87,123.91 48.38,123.41 48.38,113.75 46.86,112.23 46.86,108.67 C03.K1 | v62.1,147.28 v62.1,137.63 | v91.56,178.78 91.05,179.29 91.05,180.81 B06.J1 | v156.59,69.05 156.59,42.13 157.6,41.11 157.6,39.08 D10.K1
  Route2 0.254: v47.87,123.91 48.89,123.91 62.1,137.12 v62.1,137.63 | v62.1,147.28 63.11,148.3 63.62,148.3 80.89,165.57 80.89,168.11 v91.56,178.78
  Route15 0.254: v89.53,70.57 79.37,80.73 78.35,80.73 68.7,90.39 67.18,90.39 64.13,93.43 61.59,93.43 46.86,108.17 C03.K1
  Bottom 0.254: v156.59,69.05 155.06,70.57 138.3,70.57 137.28,69.56 136.27,69.56 134.74,71.08 111.37,71.08 110.87,70.57 v89.53,70.57
BAC_04  (via drill 0.61)
  Top 0.254: v96.64,168.62 96.13,168.11 96.13,102.58 v96.64,102.07
  Route2 0.254: C07.M2 103.25,102.07 100.2,99.02 C07.N2
  Route15 0.254: v96.64,168.62 94.1,171.16 B06.M1 | v96.64,102.07 99.69,99.02 C07.N2
BAC_04\  (via drill 0.61)
  Top 0.254: v63.62,119.34 64.13,119.85 64.13,134.58 62.1,136.61 61.08,136.61 v61.08,143.22 | v91.05,172.68 91.05,174.21 B06.L1
  Route2 0.254: v63.62,119.34 54.99,110.71 54.99,109.18 47.37,101.56 C03.M1 | v61.08,143.22 64.64,146.77 64.64,147.28 81.91,164.55 82.42,164.55 84.96,167.09 85.47,167.09 v91.05,172.68
  Route15 0.254: v145.92,38.57 131.19,53.3 131.19,54.83 129.15,56.86 129.15,57.37 113.91,72.61 110.36,72.61 96.13,86.83 96.13,89.88 88.51,97.5 87.5,97.5 86.99,98.01 86.99,98.51 79.37,106.13 77.34,106.13 71.24,112.23 70.73,112.23 v63.62,119.34
  Bottom 0.254: v145.92,38.57 151,38.57 D10.K2
BAC_05
  Bottom 0.254: 108.33,163.54 109.85,165.06 B07.P1 | 108.33,163.54 107.31,162.52 B07.R1 | 108.33,163.54 96.13,163.54 94.61,165.06 B06.P1
BAC_05\
  Route15 0.254: C03.P1 47.37,95.47 47.87,95.47 48.89,94.45 48.89,92.42 56,85.31 56,84.8 56.51,84.29 57.02,84.29 65.65,75.65 65.65,75.15 66.16,74.64 70.23,74.64 79.88,64.99 79.88,63.46 93.59,49.75 110.87,49.75 127.12,33.49 127.12,31.97 140.84,18.25 144.39,18.25 147.44,15.2 159.63,15.2 167.76,23.33 162.68,28.41 162.68,31.46 149.98,44.16 149.98,45.68 148.97,46.7 147.44,46.7 146.93,47.21 146.93,48.22 145.92,49.24 141.85,49.24 131.19,59.91 131.19,61.94 126.61,66.51 126.61,68.03 111.37,83.27 111.37,83.78 101.21,93.94 100.2,93.94 86.48,107.66 86.48,112.74 82.93,116.29 80.89,116.29 67.69,129.5 67.69,131.03 62.1,136.61 61.59,136.61 59.05,139.15 59.05,139.66 57.53,141.19 57.02,141.19 50.92,147.28 50.92,147.79 50.41,148.3 49.4,148.3 48.89,147.79 48.89,146.27 47.87,145.25 46.86,146.27 46.86,147.79 33.65,161 33.14,161 29.59,164.55 29.59,168.62 28.06,170.14 24,170.14 22.98,171.16 22.98,175.22 18.41,179.79 18.41,185.38 4.19,199.61 4.19,202.65 1.65,205.19 1.65,206.21 19.43,223.99 38.22,205.19 57.02,205.19 63.62,198.59 63.62,195.54 65.65,193.51 65.65,192.49 83.43,174.71 83.43,174.21 87.5,170.14 89.02,170.14 90.55,168.62 B06.N1
BAC_06  (via drill 0.61)
  Top 0.254: v173.35,62.45 173.35,57.87 D11.C1 | v144.9,91.91 144.39,92.42 144.39,138.14 v144.9,138.65 | v103.75,138.14 103.75,152.36 B07.U2
  Route15 0.254: 100.2,155.41 103.25,152.36 B07.U2 | 100.2,155.41 B07.T2 100.2,155.41 | v173.35,62.45 156.59,79.21 156.59,80.23 v144.9,91.91 | 100.2,155.41 96.13,159.47 94.61,159.47 B06.S1
  Bottom 0.254: v144.9,138.65 132.71,138.65 132.2,138.14 v103.75,138.14
BAC_06\
  Route2 0.254: C03.S1 46.86,88.86 46.86,87.34 34.67,75.15 34.16,75.15 33.65,74.64 33.65,70.07 29.08,65.49 29.08,64.48 22.98,58.38 22.98,54.32 19.43,50.76 19.43,47.21 17.9,45.68 17.9,34.51 35.68,16.73 36.7,17.74 117.47,17.74 133.73,1.49 180.97,1.49 182.49,3.01 200.27,3.01 225.17,27.9 225.17,30.95 238.37,44.16 238.37,45.17 284.09,90.89 285.11,90.89 301.87,107.66 301.87,110.71 317.62,126.45 317.62,130.01 347.59,159.98 350.64,159.98 363.34,172.68 365.88,172.68 379.09,185.89 380.11,185.89 419.22,225.01 419.22,264.63 411.6,272.25 399.41,272.25 379.6,292.06 212.47,292.06 178.94,258.53 178.94,257.52 168.27,246.85 164.21,246.85 162.68,245.33 162.68,242.79 150.49,230.59 150.49,226.02 116.96,192.49 114.93,192.49 107.31,184.87 107.31,183.35 99.18,175.22 99.18,174.21 96.64,171.67 96.64,170.14 93.09,166.59 93.09,164.05 91.56,162.52 B06.R1
BAC_07
  Route2 0.254: C07.D1 107.31,124.42 109.85,126.96 C07.C1
  Route15 0.254: 123.06,113.75 109.85,126.96 C07.C1 | 123.06,113.75 130.17,106.64 133.22,106.64 145.92,93.94 148.97,93.94 162.68,80.23 162.68,79.21 178.94,62.95 178.94,59.91 194.69,44.16 194.69,35.01 184.02,24.35 182.49,24.35 181.48,25.36 181.48,29.43 174.87,36.03 174.87,39.59 168.27,46.19 168.27,47.21 167.25,48.22 167.25,50.76 D11.E2 | 123.06,113.75 124.58,115.28 124.58,116.29 124.07,116.8 122.04,116.8 112.39,126.45 112.39,127.98 111.37,128.99 111.37,134.58 94.61,151.35 94.61,152.36 B06.U1
BAC_07\  (via drill 0.61)
  Top 0.254: v75.81,109.69 76.32,110.2 76.32,147.28 v75.81,147.79
  Route2 0.254: v75.81,109.69 69.21,103.09 67.18,103.09 47.37,83.27 C03.U1
  Bottom 0.254: v75.81,147.79 76.32,147.28 86.99,147.28 89.02,149.31 90.55,149.31 B06.V1
BAC_08  (via drill 0.61)
  Top 0.254: v80.89,189.95 80.39,189.45 80.39,151.35 79.37,150.33 79.37,138.14 v79.88,137.63 | v145.92,82.77 v145.92,59.91
  Route2 0.254: v80.89,189.95 84.45,193.51 B06.D2 | C07.E2 103.25,120.87 100.71,118.33 C07.F2
  Route15 0.254: v79.88,137.63 99.69,117.82 C07.F2 | v145.92,59.91 v162.68,43.14 | v145.92,82.77 127.63,101.05 127.63,102.58 v113.41,116.8
  Bottom 0.254: v162.68,43.14 165.73,43.14 167.25,41.62 170.3,41.62 D11.J1 | v113.41,116.8 103.75,116.8 102.74,117.82 100.71,117.82 C07.F2
BAC_08\
  Bottom 0.254: C03.F2 37.21,118.33 29.59,118.33 28.57,119.34 25.52,119.34 25.01,119.85 12.82,119.85 6.73,125.95 6.73,147.79 4.69,147.79 1.65,150.84 1.65,185.89 63.11,185.89 66.67,189.45 76.32,189.45 77.34,190.46 77.34,195.54 93.09,195.54 94.1,196.56 B06.C1
BAC_09  (via drill 0.61)
  Top 0.254: v84.96,183.86 84.96,186.91 B06.F2 | v97.66,171.16 97.66,168.11 96.64,167.09 96.64,118.33 v97.15,117.82
  Route15 0.254: v97.66,171.16 v84.96,183.86 | v97.15,117.82 v103.25,111.72 | C07.K1 109.34,108.67 106.8,111.21 C07.J1
  Bottom 0.254: v103.25,111.72 106.29,111.72 C07.J1
BAC_09\  (via drill 0.61)
  Route2 0.254: v17.9,131.03 17.9,131.53 35.17,148.81 35.17,149.31 49.91,164.05 51.94,164.05 59.05,171.16 59.56,171.16 60.07,171.67 60.07,172.17 66.67,178.78 66.67,179.29 67.18,179.79 69.72,179.79 77.34,187.41 v77.34,188.43
  Route15 0.254: v17.9,131.03 37.21,111.72 C03.J2
  Bottom 0.254: v77.34,188.43 81.91,188.43 83.94,190.46 87.5,190.46 B06.E2
BAC_10\  (via drill 0.61)
  Top 0.254: v88.01,182.33 88.01,183.86 B06.H2 | v143.89,259.55 143.89,241.26 v143.38,240.75
  Route2 0.254: v24.51,118.83 35.17,129.5 35.17,131.53 49.91,146.27 51.94,146.27 66.67,161 66.67,162.52 73.78,169.63 73.78,170.14 77.34,173.7 77.34,174.21 78.86,175.73 81.4,175.73 v88.01,182.33 | v143.89,259.55 148.46,264.12 A10.D2 | v143.38,240.75 143.38,240.25 129.66,226.53 127.63,226.53 107.31,206.21 107.31,204.69 101.72,199.1 100.2,199.1 88.01,186.91 88.01,184.87 B06.H2
  Route15 0.254: v24.51,118.83 37.71,105.63 C03.L2
BAC_11\  (via drill 0.61)
  Top 0.254: v101.72,142.2 101.21,141.69 101.21,133.06 102.23,132.04 102.23,107.15 103.75,105.63 103.75,104.61 102.23,103.09 102.23,78.19 101.72,77.69 v101.72,72.61
  Route2 0.254: v144.39,72.1 144.39,72.61 151.51,79.72 152.01,79.72 164.21,91.91 C11.R2 | v78.86,167.09 88.51,176.75 88.51,177.76 B06.K2
  Route15 0.254: v101.72,72.61 v98.17,76.16 | v58.54,76.16 46.35,88.35 45.84,88.35 38.22,95.97 38.22,97.5 37.21,98.51 C03.N2 | v78.86,167.09 78.86,166.59 82.42,163.03 82.42,161 101.21,142.2 v101.72,142.2
  Bottom 0.254: v144.39,72.1 143.89,71.59 138.3,71.59 137.79,72.1 111.37,72.1 110.87,72.61 v101.72,72.61 | v98.17,76.16 69.72,76.16 69.21,76.67 59.05,76.67 v58.54,76.16
BLK_IN_SYNC
  Route15 0.254: C11.E2 167.76,120.87 167.76,118.83 179.45,107.15 180.97,107.15 184.02,104.1 185.54,104.1 189.1,100.55 191.13,100.55 192.15,99.53 193.16,99.53 201.29,91.4 202.81,91.4 204.85,89.37 C13.S1
  Bottom 0.254: CD18.AP2 278,95.47 278,91.4 210.94,91.4 209.42,89.88 205.86,89.88 C13.S1
BLK_IN_SYNC\  (via drill 0.61)
  Top 0.254: v148.46,45.68 148.46,42.13 D10.J2 | v193.16,239.23 192.65,238.72 192.65,219.42 v193.16,218.91 | v226.69,183.86 226.18,183.35 226.18,153.38 225.67,152.87 225.67,135.09 226.69,134.07 226.69,132.04 226.18,131.53 226.18,116.8 v226.69,116.29
  Route2 0.254: v148.46,45.68 151,48.22 151.51,48.22 161.67,58.38 161.67,60.41 177.41,76.16 178.94,76.16 v194.18,91.4 | v226.69,116.29 224.66,116.29 224.15,115.79 223.64,115.79 223.13,115.28 223.13,112.74 219.58,109.18 219.07,109.18 212.47,102.58 211.96,102.58 207.39,98.01 207.39,95.47 205.35,93.43 203.32,93.43 202.31,92.42 C13.R1
  Route15 0.254: v193.16,239.23 193.16,240.25 183,250.41 182.49,250.41 181.99,250.91 181.99,251.42 174.87,258.53 173.86,258.53 171.32,261.07 170.3,261.07 158.11,273.27 A10.A1 | v193.16,218.91 193.67,218.91 206.88,205.7 206.88,202.65 225.67,183.86 v226.69,183.86
  Bottom 0.254: v194.18,91.4 197.73,91.4 198.75,92.42 201.8,92.42 C13.R1
BMB_00
  Bottom 0.254: C06.B1 91.56,130.01 92.07,129.5 117.98,129.5 118.99,130.52 122.55,130.52 C08.B1
BMB_00\
  Bottom 0.254: C02.B1 28.06,130.01 28.57,129.5 46.35,129.5 47.87,131.03 50.41,131.03 51.94,129.5 80.39,129.5 82.93,132.04 99.69,132.04 100.2,132.55 100.2,134.07 94.61,134.07 C06.A1
BMB_01
  Bottom 0.254: C06.E1 94.61,120.87 98.67,120.87 99.18,121.37 99.18,122.39 104.77,122.39 107.31,119.85 117.47,119.85 122.55,114.77 125.6,114.77 C08.H1
BMB_01\  (via drill 0.61)
  Route2 0.254: v24,132.04 24,131.53 16.38,123.91 v15.87,123.91
  Route15 0.254: v109.85,122.9 105.28,127.47 105.28,127.98 100.2,133.06 v99.18,133.06
  Bottom 0.254: v109.85,122.9 92.58,122.9 91.56,123.91 C06.D1 | v99.18,133.06 98.67,132.55 86.48,132.55 85.47,133.57 80.39,133.57 79.88,133.06 79.88,132.55 39.24,132.55 38.22,133.57 33.14,133.57 32.13,132.55 24.51,132.55 v24,132.04 | v15.87,123.91 19.43,123.91 20.44,122.9 25.52,122.9 27.05,121.37 30.6,121.37 C02.E1
BMB_02
  Bottom 0.254: C06.H1 94.61,114.26 102.23,106.64 117.47,106.64 117.98,106.13 117.98,103.09 116.96,103.09 116.45,102.58 116.45,100.04 122.04,100.04 122.55,99.53 C08.N1
BMB_02\  (via drill 0.61)
  Top 0.254: v91.05,121.88 91.05,118.33 C06.F1
  Route2 0.254: v38.22,122.39 31.11,115.28 C02.H1
  Bottom 0.254: v38.22,122.39 38.73,122.9 64.13,122.9 65.15,121.88 70.23,121.88 71.24,122.9 89.02,122.9 90.04,121.88 v91.05,121.88
BMB_03
  Bottom 0.254: C06.K1 94.1,108.67 94.1,113.25 93.59,113.25 93.09,113.75 93.09,117.82 95.63,117.82 97.15,116.29 112.39,116.29 115.95,112.74 126.11,112.74 127.12,113.75 127.12,119.85 121.03,119.85 120.01,120.87 C08.E2
BMB_03\
  Bottom 0.254: C02.K1 31.11,108.17 32.13,107.15 79.88,107.15 83.43,110.71 83.43,116.29 88.51,116.29 90.55,114.26 90.55,112.23 C06.J1
BMB_04
  Bottom 0.254: C06.M1 94.61,102.58 96.13,104.1 115.44,104.1 115.95,104.61 C08.L2
BMB_04\
  Bottom 0.254: C02.M1 31.11,102.58 38.73,102.58 40.25,104.1 90.04,104.1 90.55,104.61 C06.L1
BMB_05
  Bottom 0.254: C06.P1 94.61,95.47 99.18,90.89 118.49,90.89 119.5,89.88 C08.S2
BMB_05\
  Bottom 0.254: C02.P1 31.11,95.47 32.13,94.45 43.3,94.45 45.84,96.99 52.45,96.99 54.99,94.45 79.37,94.45 81.4,92.42 82.42,92.42 83.94,93.94 83.94,97.5 89.53,97.5 90.55,98.51 C06.N1
BMB_06  (via drill 0.61)
  Top 0.254: v117.98,114.26 118.49,114.77 118.49,160.49 119.5,161.51 119.5,163.03 118.49,164.05 118.49,168.62 117.47,169.63 117.47,172.68 117.98,173.19 117.98,174.21 118.49,174.71 v118.49,200.11
  Route2 0.254: v117.98,114.26 117.47,114.26 115.44,112.23 115.44,111.72 114.93,111.21 114.93,109.69 104.77,99.53 104.77,99.02 104.26,98.51 103.25,98.51 94.61,89.88 C06.S1
  Bottom 0.254: v118.49,200.11 122.55,200.11 B08.B1
BMB_06\
  Bottom 0.254: C02.S1 31.11,89.88 32.63,91.4 90.04,91.4 90.55,91.91 C06.R1
BMB_07  (via drill 0.61)
  Top 0.254: v107.82,96.48 107.82,103.09 108.33,103.59 108.33,131.53 107.31,132.55 107.31,147.28 108.83,148.81 108.83,180.3 v109.34,180.81
  Route2 0.254: v107.82,96.48 94.61,83.27 C06.U1 | v112.39,180.81 v122.04,190.46
  Bottom 0.254: v109.34,180.81 v112.39,180.81 | v122.04,190.46 125.6,190.46 B08.E1
BMB_07\
  Bottom 0.254: C02.U1 31.11,82.77 35.17,78.7 90.04,78.7 90.55,79.21 C06.V1
BMB_08  (via drill 0.61)
  Top 0.254: v84.96,128.49 84.96,124.93 C06.D2 | v114.42,163.03 114.93,163.54 v114.93,190.46
  Route2 0.254: v84.96,128.49 89.02,132.55 89.02,135.09 97.66,143.73 98.17,143.73 112.39,157.95 112.39,161 v114.42,163.03
  Bottom 0.254: v114.93,190.46 119.5,190.46 B08.E2
BMB_08\  (via drill 0.61)
  Top 0.254: v94.1,124.93 94.1,126.96 C06.C1
  Route2 0.254: v47.37,116.8 48.38,116.8 v75.31,143.73
  Route15 0.254: v75.31,143.73 80.89,138.14 80.89,137.63 93.59,124.93 v94.1,124.93
  Bottom 0.254: v47.37,116.8 21.97,116.8 21.46,117.31 C02.F2
BMB_09  (via drill 0.61)
  Top 0.254: v82.42,115.28 82.42,127.47 82.93,127.98 82.93,129.5 v82.42,130.01
  Route2 0.254: v82.42,115.28 84.96,117.82 C06.F2 | v82.42,130.01 83.43,131.03 83.43,131.53 92.07,140.17 92.07,142.71 113.41,164.05 114.42,164.05 v122.04,171.67
  Bottom 0.254: v122.04,171.67 125.6,171.67 B08.M1
BMB_09\  (via drill 0.61)
  Top 0.254: v18.92,113.75 19.43,114.26 19.43,136.11 v18.92,136.61
  Route15 0.254: v18.92,113.75 20.95,111.72 C02.J2 | v71.24,137.12 71.75,137.12 81.91,126.96 81.91,124.42 v84.96,121.37
  Bottom 0.254: v18.92,136.61 20.44,138.14 36.7,138.14 38.22,136.61 46.86,136.61 48.38,138.14 54.48,138.14 56,136.61 70.73,136.61 v71.24,137.12 | v84.96,121.37 87.5,121.37 C06.E2
BMB_10  (via drill 0.61)
  Top 0.254: v98.17,121.88 97.66,122.39 97.66,142.2 v98.17,142.71
  Route2 0.254: v98.17,121.88 v88.01,111.72 | v98.17,142.71 115.44,159.98 116.45,159.98 v118.49,162.01
  Bottom 0.254: v88.01,111.72 84.96,111.72 C06.J2 | v118.49,162.01 122.55,162.01 B08.R1
BMB_10\
  Bottom 0.254: C02.L2 21.46,105.63 22.98,107.15 27.05,107.15 29.59,109.69 74.29,109.69 75.31,108.67 76.32,108.67 76.83,109.18 76.83,116.8 89.02,116.8 92.58,113.25 92.58,110.2 90.04,110.2 89.02,111.21 89.02,114.26 88.51,114.26 C06.H2
BMB_11  (via drill 0.61)
  Top 0.254: v84.96,109.69 84.96,105.63 C06.L2 | v98.67,123.91 98.17,124.42 98.17,141.19 99.18,142.2 99.18,154.9 v98.67,155.41 | v123.06,179.29 123.06,180.81 B08.J1
  Route2 0.254: v84.96,109.69 86.99,111.72 86.99,112.23 87.5,112.74 88.01,112.74 97.15,121.88 97.15,122.39 v98.67,123.91 | v98.67,155.41 98.67,155.92 111.88,169.13 112.9,169.13 v123.06,179.29
BMB_11\
  Bottom 0.254: C02.N2 21.46,99.53 22.47,100.55 88.51,100.55 92.58,104.61 92.58,108.17 88.51,108.17 C06.K2
BMB_TO_DTB
  Top 0.254: 124.07,128.99 124.07,119.34 123.06,118.33 C08.F1 | 124.07,128.99 124.07,132.04 125.6,133.57 C08.A1 125.6,134.07 124.58,135.09 124.58,166.59 | 124.58,166.59 124.07,167.09 124.07,173.19 | 124.58,166.59 125.6,165.57 B08.P1 | 124.07,173.19 123.06,174.21 B08.L1 | 124.07,192.49 124.07,186.4 125.6,184.87 B08.H1 126.61,183.86 127.12,183.35 127.12,176.24 124.07,173.19 | 124.07,192.49 123.06,193.51 B08.D1 | 124.07,192.49 124.07,201.64 125.6,203.16 B08.A1 | 124.07,128.99 127.12,128.99 127.12,103.09 126.61,102.58 C08.M1
  Route15 0.254: D12.L1 186.56,36.03 186.56,38.57 178.43,46.7 178.43,48.73 153.03,74.13 152.01,74.13 146.93,79.21 146.93,80.23 126.11,101.05 126.11,101.56 C08.M1
  Bottom 0.254: C08.F1 122.55,118.33 121.53,119.34 118.99,119.34 116.96,121.37 116.96,123.91 C08.D2 | B08.D2 116.96,193.51 122.55,193.51 B08.D1 | C08.R2 116.96,92.93 116.96,97.5 124.07,97.5 125.6,99.02 125.6,101.56 C08.M1 125.6,102.58 124.58,103.59 119.5,103.59 119.5,108.17 C08.K2
BMR00  (via drill 0.61)
  Route2 0.254: v236.34,187.92 227.2,178.78 226.69,178.78 217.04,169.13 217.04,168.11 214.5,165.57 B14.P2 | v241.93,187.92 243.96,189.95 243.96,190.46 265.3,211.8 v265.81,211.8 | v312.03,210.78 337.43,236.18 338.45,236.18 352.67,250.41 352.67,250.91 359.79,258.03 360.8,258.03 A23.F1
  Bottom 0.254: v241.93,187.92 v236.34,187.92 | v265.81,211.8 274.44,211.8 275.97,210.27 311.53,210.27 v312.03,210.78
BMR00\
  Route2 0.254: B14.R2 211.96,162.52 214.5,162.52 220.59,168.62 222.63,168.62 224.15,167.09 239.39,182.33 242.95,182.33 252.6,191.99 254.12,191.99 270.89,208.75 272.92,208.75 286.13,221.96 286.13,222.97 299.84,236.69 300.86,236.69 317.62,253.45 317.62,254.47 331.85,268.69 334.89,268.69 337.94,271.74 348.1,271.74 348.61,272.25 349.63,272.25 365.88,255.99 364.87,254.98 A23.H1
BMR01  (via drill 0.61)
  Top 0.254: v256.66,216.88 256.15,217.39 256.15,240.75 256.66,241.26 v256.66,275.81 | v361.31,275.3 361.31,270.73 A23.B1
  Route2 0.254: v228.21,189.45 228.21,189.95 228.72,190.46 228.72,190.97 236.85,199.1 238.88,199.1 239.39,199.61 239.39,200.11 256.15,216.88 v256.66,216.88
  Bottom 0.254: v228.21,189.45 225.67,189.45 224.66,188.43 219.07,188.43 218.56,187.92 B14.F1 | v256.66,275.81 257.17,275.3 v361.31,275.3
BMR01\  (via drill 0.61)
  Top 0.254: v222.63,210.27 223.13,209.77 223.13,201.64 222.63,201.13 222.63,192.49 222.12,191.99 222.12,191.48 221.61,190.97 B14.E1 | v257.17,222.47 256.66,222.97 256.66,240.25 257.17,240.75 257.17,274.79 257.68,275.3 v257.68,276.82
  Route2 0.254: v245.99,211.29 246.5,211.29 257.17,221.96 v257.17,222.47
  Bottom 0.254: v222.63,210.27 223.13,209.77 239.9,209.77 241.42,211.29 v245.99,211.29 | v257.68,276.82 257.68,275.81 360.29,275.81 360.8,276.31 361.82,276.31 362.33,275.81 362.33,273.77 363.85,273.77 A23.A1
C00  (via drill 0.61)
  Top 0.254: v219.07,134.07 218.56,134.58 218.56,144.74 v219.07,145.25 | v177.41,77.18 176.91,77.69 176.91,100.55 177.92,101.56 177.92,113.75 178.94,114.77 178.94,136.11 177.92,137.12 177.92,150.33 178.94,151.35 v178.94,157.95 179.95,158.97 179.95,161.51 B12.R2 179.95,162.52 179.95,164.55 178.94,165.57 178.94,201.13 179.95,202.15 179.95,216.88 178.43,218.4 178.43,239.23 179.95,240.75 179.95,244.31 A12.L2 179.95,245.33 179.95,247.36 177.92,249.39 v177.92,290.54 | v398.9,263.11 398.39,263.61 398.39,290.03 v398.9,290.54
  Route2 0.254: v177.41,77.18 158.11,57.87 D10.C1 | v204.34,157.44 205.35,158.46 B13.S1
  Route15 0.254: v219.07,134.07 220.59,132.55 221.1,132.55 231.26,122.39 231.26,121.37 C15.E2 | v219.07,145.25 205.86,158.46 B13.S1 | v398.9,263.11 v400.93,261.07
  Bottom 0.254: v400.93,261.07 405,261.07 A26.E2 | v398.9,290.54 397.38,290.54 396.36,291.55 192.65,291.55 191.64,290.54 v177.92,290.54 | v204.34,157.44 179.45,157.44 v178.94,157.95
C00\  (via drill 0.61)
  Top 0.254: B13.P1 205.86,165.06 205.86,161 206.88,159.98 206.88,155.92 205.86,154.9 205.86,152.87 B13.U1 | v225.17,113.75 v225.17,133.06 | v199.26,161.51 199.26,159.47 B13.S2 | v183,232.12 183,235.17 A12.P2 | v207.89,205.7 207.89,185.38 208.91,184.37 v208.91,179.79 v208.91,168.11
  Route2 0.254: v202.81,165.06 v199.26,161.51 | v208.91,168.11 205.86,165.06 B13.P1 | v230.25,179.79 v234.82,184.37
  Route15 0.254: v225.17,113.75 227.2,111.72 C15.J2 | v225.17,133.06 205.86,152.36 B13.U1 | v183,232.12 193.67,221.45 193.67,219.93 v207.89,205.7
  Bottom 0.254: v202.81,165.06 205.35,165.06 B13.P1 | v234.82,184.37 236.85,184.37 B15.H1 | v208.91,179.79 v230.25,179.79
C01  (via drill 0.61)
  Top 0.254: 160.65,180.81 v160.65,181.32 | 160.65,180.81 160.65,164.55 | 160.65,164.55 v160.65,152.36 | 160.65,164.55 v160.14,164.55 | v174.37,238.21 175.38,237.2 175.38,221.96 174.87,221.45 v174.87,216.37 | v160.14,201.13 160.14,188.43 159.63,187.92 159.63,186.91 161.16,185.38 161.16,181.32 160.65,180.81 | v399.92,254.98 399.41,254.47 399.41,245.83 399.92,245.33 v399.92,225.01
  Route2 0.254: v174.37,238.21 v177.92,241.77 | v174.87,216.37 174.87,215.86 v160.14,201.13 | v399.92,254.98 402.46,257.52 A26.F2 | v399.92,225.01 399.92,224.5 389.76,214.34 v389.25,214.34
  Route15 0.254: v160.65,152.36 163.7,149.31 B11.V2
